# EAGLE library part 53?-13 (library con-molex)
CONNECTOR wire to board 1.25 mm (.049 inch) pitch header

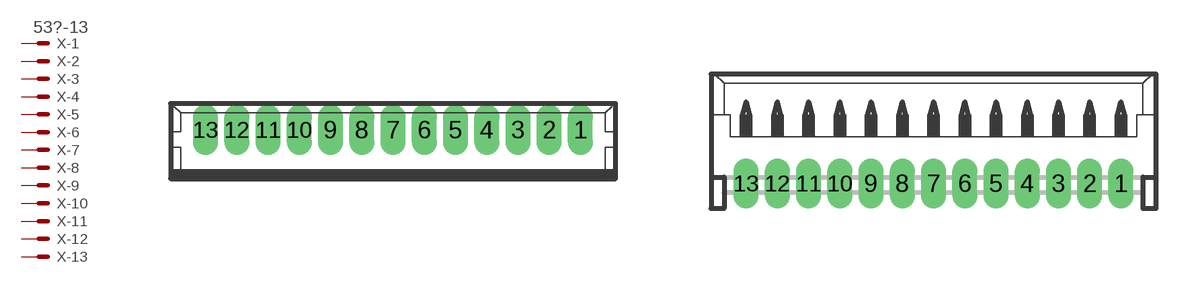
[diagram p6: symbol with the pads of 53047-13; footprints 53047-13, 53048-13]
Designator prefix X; gates -1=MV -2=M -3=M -4=M -5=M -6=M -7=M -8=M -9=M -10=M -11=M -12=M -13=M

## 53047-13 (MPN: 53047-1310-C; OC_FARNELL: 1012238; OC_NEWARK: 03N7646)  [53047-13]
1  -1:S  pas
2  -2:S  pas
3  -3:S  pas
4  -4:S  pas
5  -5:S  pas
6  -6:S  pas
7  -7:S  pas
8  -8:S  pas
9  -9:S  pas
10  -10:S  pas
11  -11:S  pas
12  -12:S  pas
13  -13:S  pas

## 53048-13 (MPN: 53048-1310-C; OC_FARNELL: unknown; OC_NEWARK: 03N7647)  [53048-13]
Pads as for 53047-13

## 53261-13 (MPN: 53261-1371; OC_FARNELL: 1756927; OC_NEWARK: 92M6827)  [53261-13]
Pads as for 53047-13

## 53398-13 (OC_FARNELL: unknown; OC_NEWARK: unknown)  [53398-13]
Pads as for 53047-13

## Footprint 53047-13 (pad centres in mm)
CONNECTOR wire to board 1.25 mm (.049 inch) pitch header straight Sourcxe: http://www.molex.com/pdm_docs/sd/530470210_sd.pdf
drill 0.5 pad 0.698 long: 1 7.5,0.45; 2 6.25,0.45; 3 5,0.45; 4 3.75,0.45; 5 2.5,0.45; 6 1.25,0.45; 7 0,0.45; 8 -1.25,0.45; 9 -2.5,0.45; 10 -3.75,0.45; 11 -5,0.45; 12 -6.25,0.45; 13 -7.5,0.45

## Footprint 53048-13 (pad centres in mm)
CONNECTOR wire to board 1.25 mm (.049 inch) pitch header right angle
drill 0.5 pad 0.698 long: 1 7.5,-1.25; 2 6.25,-1.25; 3 5,-1.25; 4 3.75,-1.25; 5 2.5,-1.25; 6 1.25,-1.25; 7 0,-1.25; 8 -1.25,-1.25; 9 -2.5,-1.25; 10 -3.75,-1.25; 11 -5,-1.25; 12 -6.25,-1.25; 13 -7.5,-1.25

## Footprint 53261-13 (pad centres in mm)
CONNECTOR wire to board 1.25 mm (.049 inch) pitch header SMT right angle
smd 0.8 x 2: 1 7.5,-2.5; 2 6.25,-2.5; 3 5,-2.5; 4 3.75,-2.5; 5 2.5,-2.5; 6 1.25,-2.5; 7 0,-2.5; 8 -1.25,-2.5; 9 -2.5,-2.5; 10 -3.75,-2.5; 11 -5,-2.5; 12 -6.25,-2.5; 13 -7.5,-2.5
smd 2.1 x 3: S1 10,0.625; S2 -10,0.625

## Footprint 53398-13 (pad centres in mm)
CONNECTOR wire to board 1.25 mm (.049 inch) pitch header SMT straight
smd 0.8 x 1.8: 1 7.5,-2.5; 2 6.25,-2.5; 3 5,-2.5; 4 3.75,-2.5; 5 2.5,-2.5; 6 1.25,-2.5; 7 0,-2.5; 8 -1.25,-2.5; 9 -2.5,-2.5; 10 -3.75,-2.5; 11 -5,-2.5; 12 -6.25,-2.5; 13 -7.5,-2.5
smd 2.1 x 3: S1 10,0.625; S2 -10,0.625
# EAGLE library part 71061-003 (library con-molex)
CONNECTOR 68-pin 1.27mm (.050 inch) pitch SCSI+ unshielded receptacle right angle all plastic

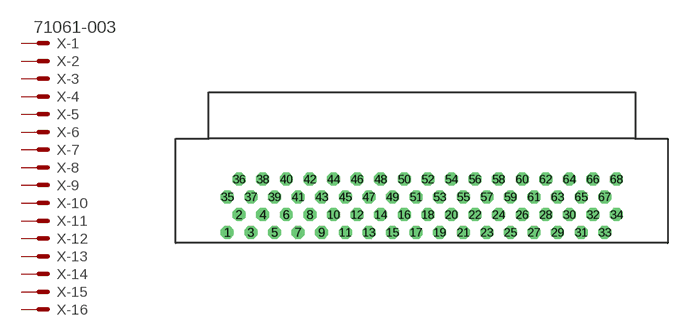
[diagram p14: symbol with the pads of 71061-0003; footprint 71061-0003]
Designator prefix X; gates -1=MV -2=M -3=M -4=M -5=M -6=M -7=M -8=M -9=M -10=M -11=M -12=M -13=M -14=M -15=M -16=M -17=M -18=M -19=M -20=M -21=M -22=M -23=M -24=M -25=M -26=M -27=M -28=M -29=M -30=M -31=M -32=M -33=M -34=M -35=M -36=M -37=M -38=M -39=M -40=M -41=M -42=M -43=M -44=M -45=M -46=M -47=M -48=M -49=M -50=M -51=M -52=M -53=M -54=M -55=M -56=M -57=M -58=M -59=M -60=M -61=M -62=M -63=M -64=M -65=M -66=M -67=M -68=M

## 71061-003 (OC_FARNELL: unknown; OC_NEWARK: unknown)  [71061-0003]
1  -1:S  pas
2  -2:S  pas
3  -3:S  pas
4  -4:S  pas
5  -5:S  pas
6  -6:S  pas
7  -7:S  pas
8  -8:S  pas
9  -9:S  pas
10  -10:S  pas
11  -11:S  pas
12  -12:S  pas
13  -13:S  pas
14  -14:S  pas
15  -15:S  pas
16  -16:S  pas
17  -17:S  pas
18  -18:S  pas
19  -19:S  pas
20  -20:S  pas
21  -21:S  pas
22  -22:S  pas
23  -23:S  pas
24  -24:S  pas
25  -25:S  pas
26  -26:S  pas
27  -27:S  pas
28  -28:S  pas
29  -29:S  pas
30  -30:S  pas
31  -31:S  pas
32  -32:S  pas
33  -33:S  pas
34  -34:S  pas
35  -35:S  pas
36  -36:S  pas
37  -37:S  pas
38  -38:S  pas
39  -39:S  pas
40  -40:S  pas
41  -41:S  pas
42  -42:S  pas
43  -43:S  pas
44  -44:S  pas
45  -45:S  pas
46  -46:S  pas
47  -47:S  pas
48  -48:S  pas
49  -49:S  pas
50  -50:S  pas
51  -51:S  pas
52  -52:S  pas
53  -53:S  pas
54  -54:S  pas
55  -55:S  pas
56  -56:S  pas
57  -57:S  pas
58  -58:S  pas
59  -59:S  pas
60  -60:S  pas
61  -61:S  pas
62  -62:S  pas
63  -63:S  pas
64  -64:S  pas
65  -65:S  pas
66  -66:S  pas
67  -67:S  pas
68  -68:S  pas

## Footprint 71061-0003 (pad centres in mm)
CONNECTOR 68-pin 1.27mm (.050 inch) pitch SCSI+ unshielded receptacle, right angle, all plastic Source: http://www.molex.com/product/io/71061.html http://www.molex.com .. 710610003_sd.pdf
drill 0.813 pad 1.397 octagon: 1 -20.955,-5.73; 2 -19.685,-3.82; 3 -18.415,-5.73; 4 -17.145,-3.82; 5 -15.875,-5.73; 6 -14.605,-3.82; 7 -13.335,-5.73; 8 -12.065,-3.82; 9 -10.795,-5.73; 10 -9.525,-3.82; 11 -8.255,-5.73; 12 -6.985,-3.82; 13 -5.715,-5.73; 14 -4.445,-3.82; 15 -3.175,-5.73; 16 -1.905,-3.82; 17 -0.635,-5.73; 18 0.635,-3.82; 19 1.905,-5.73; 20 3.175,-3.82; 21 4.445,-5.73; 22 5.715,-3.82; 23 6.985,-5.73; 24 8.255,-3.82; 25 9.525,-5.73; 26 10.795,-3.82; 27 12.065,-5.73; 28 13.335,-3.82; 29 14.605,-5.73; 30 15.875,-3.82; 31 17.145,-5.73; 32 18.415,-3.82; 33 19.685,-5.73; 34 20.955,-3.82; 35 -20.955,-1.91; 36 -19.685,0; 37 -18.415,-1.91; 38 -17.145,0; 39 -15.875,-1.91; 40 -14.605,0; 41 -13.335,-1.91; 42 -12.065,0; 43 -10.795,-1.91; 44 -9.525,0; 45 -8.255,-1.91; 46 -6.985,0; 47 -5.715,-1.91; 48 -4.445,0; 49 -3.175,-1.91; 50 -1.905,0; 51 -0.635,-1.91; 52 0.635,0; 53 1.905,-1.91; 54 3.175,0; 55 4.445,-1.91; 56 5.715,0; 57 6.985,-1.91; 58 8.255,0; 59 9.525,-1.91; 60 10.795,0; 61 12.065,-1.91; 62 13.335,0; 63 14.605,-1.91; 64 15.875,0; 65 17.145,-1.91; 66 18.415,0; 67 19.685,-1.91; 68 20.955,0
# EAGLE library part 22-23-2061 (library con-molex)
.100" (2.54mm) Center Header - 6 Pin

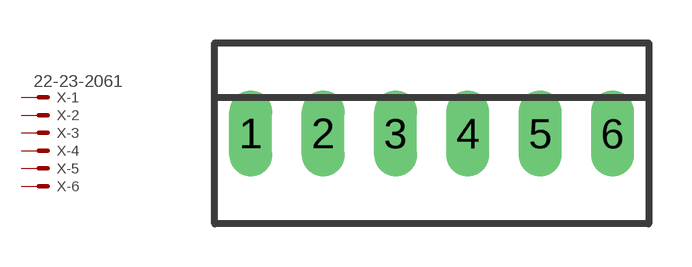
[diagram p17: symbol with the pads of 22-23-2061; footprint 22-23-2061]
Designator prefix X; gates -1=MV -2=M -3=M -4=M -5=M -6=M

## 22-23-2061 (MF: MOLEX; MPN: 22-23-2061; OC_FARNELL: 1462922; OC_NEWARK: 27C1933)  [22-23-2061]
1  -1:S  pas
2  -2:S  pas
3  -3:S  pas
4  -4:S  pas
5  -5:S  pas
6  -6:S  pas

## Footprint 22-23-2061 (pad centres in mm)
.100" (2.54mm) Center Header - 6 Pin
drill 1 long: 1 -6.35,0; 2 -3.81,0; 3 -1.27,0; 4 1.27,0; 5 3.81,0; 6 6.35,0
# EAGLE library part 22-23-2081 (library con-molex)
.100" (2.54mm) Center Header - 8 Pin

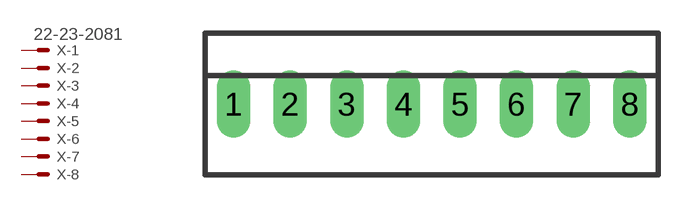
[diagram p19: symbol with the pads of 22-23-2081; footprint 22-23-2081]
Designator prefix X; gates -1=MV -2=M -3=M -4=M -5=M -6=M -7=M -8=M

## 22-23-2081 (MF: MOLEX; MPN: 22-23-2081; OC_FARNELL: 1756826; OC_NEWARK: 01C7592)  [22-23-2081]
1  -1:S  pas
2  -2:S  pas
3  -3:S  pas
4  -4:S  pas
5  -5:S  pas
6  -6:S  pas
7  -7:S  pas
8  -8:S  pas

## Footprint 22-23-2081 (pad centres in mm)
.100" (2.54mm) Center Header - 8 Pin
drill 1 long: 1 -8.89,0; 2 -6.35,0; 3 -3.81,0; 4 -1.27,0; 5 1.27,0; 6 3.81,0; 7 6.35,0; 8 8.89,0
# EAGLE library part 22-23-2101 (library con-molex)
.100" (2.54mm) Center Header - 10 Pin

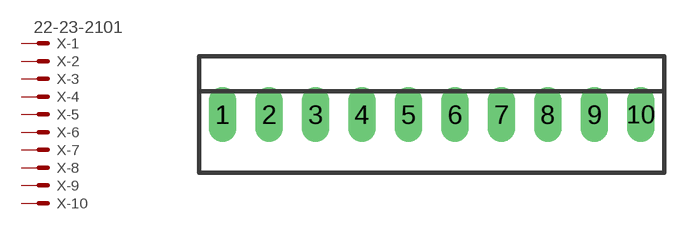
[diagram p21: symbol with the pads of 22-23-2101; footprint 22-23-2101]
Designator prefix X; gates -1=MV -2=M -3=M -4=M -5=M -6=M -7=M -8=M -9=M -10=M

## 22-23-2101 (MF: MOLEX; MPN: 22-23-2101; OC_FARNELL: 1756828; OC_NEWARK: 94C0765)  [22-23-2101]
1  -1:S  pas
2  -2:S  pas
3  -3:S  pas
4  -4:S  pas
5  -5:S  pas
6  -6:S  pas
7  -7:S  pas
8  -8:S  pas
9  -9:S  pas
10  -10:S  pas

## Footprint 22-23-2101 (pad centres in mm)
.100" (2.54mm) Center Header - 10 Pin
drill 1 long: 1 -11.43,0; 2 -8.89,0; 3 -6.35,0; 4 -3.81,0; 5 -1.27,0; 6 1.27,0; 7 3.81,0; 8 6.35,0; 9 8.89,0; 10 11.43,0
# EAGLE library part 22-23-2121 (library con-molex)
.100" (2.54mm) Center Header - 12 Pin

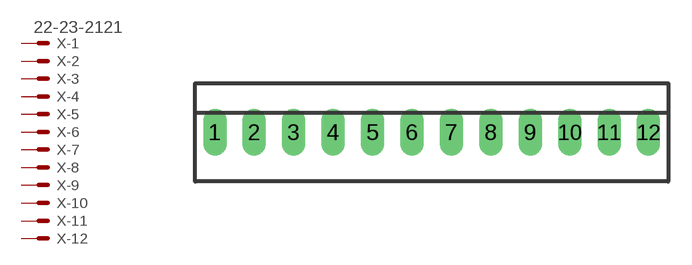
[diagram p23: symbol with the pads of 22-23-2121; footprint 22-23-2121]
Designator prefix X; gates -1=MV -2=M -3=M -4=M -5=M -6=M -7=M -8=M -9=M -10=M -11=M -12=M

## 22-23-2121 (MF: MOLEX; MPN: 22-23-2121; OC_FARNELL: 1462935; OC_NEWARK: 56H0456)  [22-23-2121]
1  -1:S  pas
2  -2:S  pas
3  -3:S  pas
4  -4:S  pas
5  -5:S  pas
6  -6:S  pas
7  -7:S  pas
8  -8:S  pas
9  -9:S  pas
10  -10:S  pas
11  -11:S  pas
12  -12:S  pas

## Footprint 22-23-2121 (pad centres in mm)
.100" (2.54mm) Center Header - 12 Pin
drill 1 long: 1 -13.97,0; 2 -11.43,0; 3 -8.89,0; 4 -6.35,0; 5 -3.81,0; 6 -1.27,0; 7 1.27,0; 8 3.81,0; 9 6.35,0; 10 8.89,0; 11 11.43,0; 12 13.97,0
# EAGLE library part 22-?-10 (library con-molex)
CONNECTOR wire to board 2.54 mm (.1 inch) pitch header

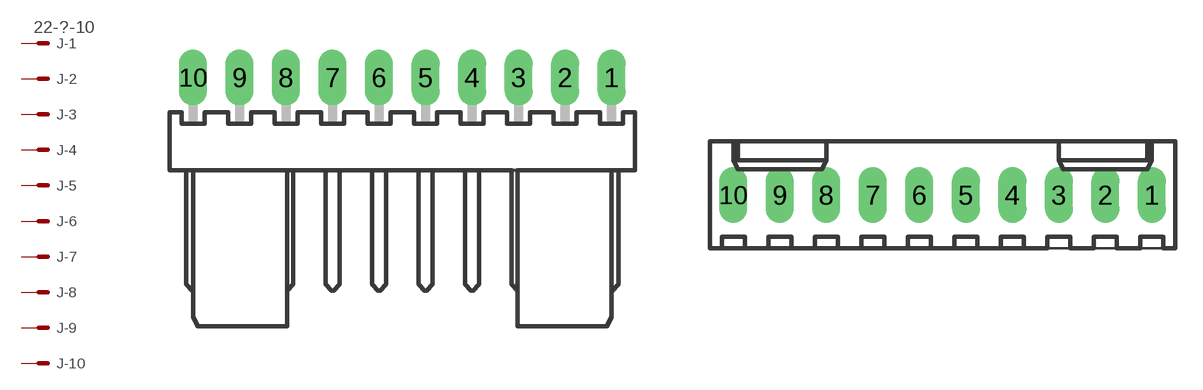
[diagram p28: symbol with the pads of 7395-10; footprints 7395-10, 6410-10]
Designator prefix J; gates -1=MV -2=M -3=M -4=M -5=M -6=M -7=M -8=M -9=M -10=M

## 22-05-7108-10 (OC_FARNELL: unknown; OC_NEWARK: unknown)  [7395-10]
1  -1:S  pas
2  -2:S  pas
3  -3:S  pas
4  -4:S  pas
5  -5:S  pas
6  -6:S  pas
7  -7:S  pas
8  -8:S  pas
9  -9:S  pas
10  -10:S  pas

## 22-27-2101-10 (OC_FARNELL: unknown; OC_NEWARK: unknown)  [6410-10]
Pads as for 7395-10

## Footprint 7395-10 (pad centres in mm)
MOLEX 2.54mm KK RA CONNECTOR Fixed Orientation
drill 1.016 long: 1 11.43,0; 2 8.89,0; 3 6.35,0; 4 3.81,0; 5 1.27,0; 6 -1.27,0; 7 -3.81,0; 8 -6.35,0; 9 -8.89,0; 10 -11.43,0

## Footprint 6410-10 (pad centres in mm)
MOLEX 2.54mm KK CONNECTOR
drill 1.016 long: 1 11.43,0; 2 8.89,0; 3 6.35,0; 4 3.81,0; 5 1.27,0; 6 -1.27,0; 7 -3.81,0; 8 -6.35,0; 9 -8.89,0; 10 -11.43,0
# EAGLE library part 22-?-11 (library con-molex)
CONNECTOR wire to board 2.54 mm (.1 inch) pitch header

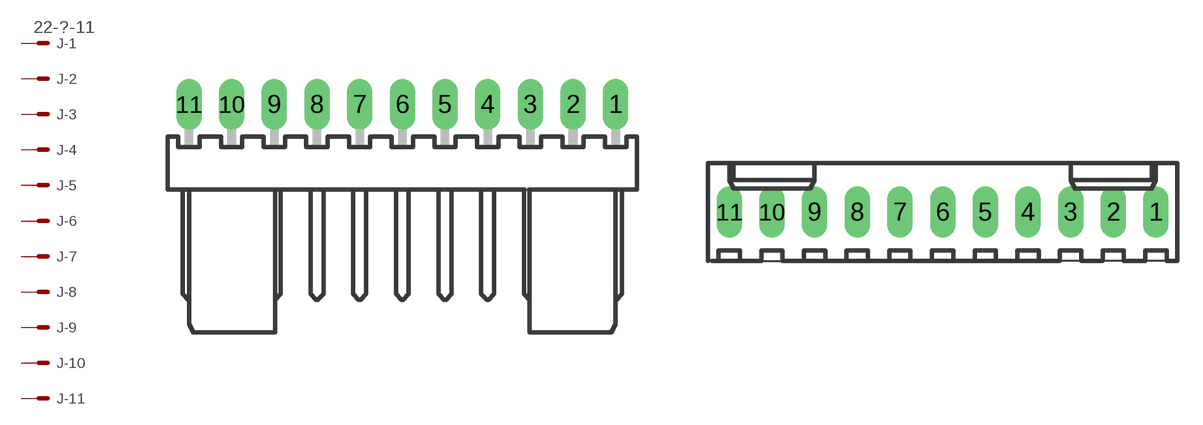
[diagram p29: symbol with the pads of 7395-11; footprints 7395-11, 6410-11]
Designator prefix J; gates -1=MV -2=M -3=M -4=M -5=M -6=M -7=M -8=M -9=M -10=M -11=M

## 22-05-7118-11 (OC_FARNELL: unknown; OC_NEWARK: unknown)  [7395-11]
1  -1:S  pas
2  -2:S  pas
3  -3:S  pas
4  -4:S  pas
5  -5:S  pas
6  -6:S  pas
7  -7:S  pas
8  -8:S  pas
9  -9:S  pas
10  -10:S  pas
11  -11:S  pas

## 22-27-2111-11 (OC_FARNELL: unknown; OC_NEWARK: unknown)  [6410-11]
Pads as for 7395-11

## Footprint 7395-11 (pad centres in mm)
MOLEX 2.54mm KK RA CONNECTOR Fixed Orientation
drill 1.016 long: 1 12.7,0; 2 10.16,0; 3 7.62,0; 4 5.08,0; 5 2.54,0; 6 0,0; 7 -2.54,0; 8 -5.08,0; 9 -7.62,0; 10 -10.16,0; 11 -12.7,0

## Footprint 6410-11 (pad centres in mm)
MOLEX 2.54mm KK CONNECTOR
drill 1.016 long: 1 12.7,0; 2 10.16,0; 3 7.62,0; 4 5.08,0; 5 2.54,0; 6 0,0; 7 -2.54,0; 8 -5.08,0; 9 -7.62,0; 10 -10.16,0; 11 -12.7,0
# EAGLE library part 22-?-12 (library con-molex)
CONNECTOR wire to board 2.54 mm (.1 inch) pitch header

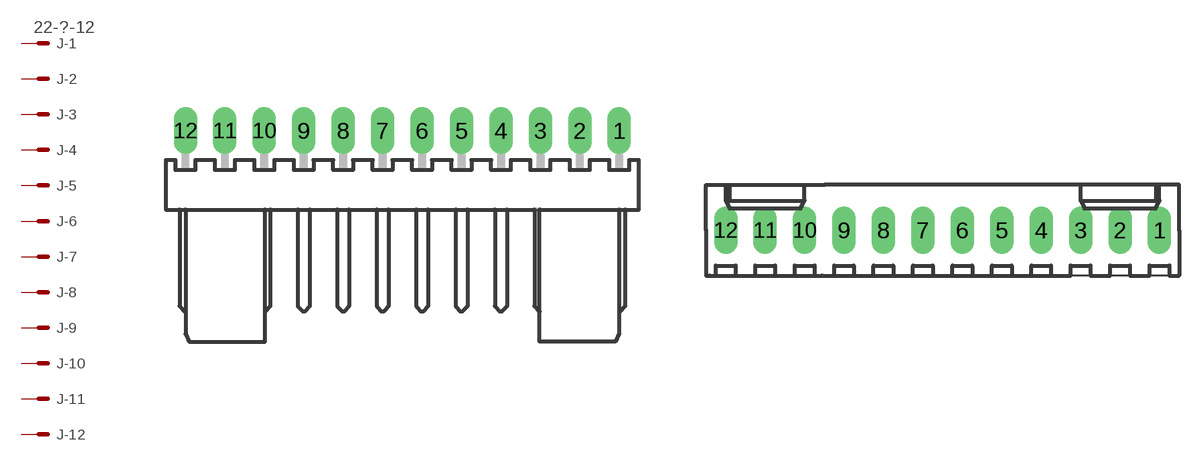
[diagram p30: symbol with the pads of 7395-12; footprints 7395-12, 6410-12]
Designator prefix J; gates -1=MV -2=M -3=M -4=M -5=M -6=M -7=M -8=M -9=M -10=M -11=M -12=M

## 22-05-7128-12 (OC_FARNELL: unknown; OC_NEWARK: unknown)  [7395-12]
1  -1:S  pas
2  -2:S  pas
3  -3:S  pas
4  -4:S  pas
5  -5:S  pas
6  -6:S  pas
7  -7:S  pas
8  -8:S  pas
9  -9:S  pas
10  -10:S  pas
11  -11:S  pas
12  -12:S  pas

## 22-27-2121-12 (OC_FARNELL: unknown; OC_NEWARK: unknown)  [6410-12]
Pads as for 7395-12

## Footprint 7395-12 (pad centres in mm)
MOLEX 2.54mm KK RA CONNECTOR Fixed Orientation
drill 1.016 long: 1 13.97,0; 2 11.43,0; 3 8.89,0; 4 6.35,0; 5 3.81,0; 6 1.27,0; 7 -1.27,0; 8 -3.81,0; 9 -6.35,0; 10 -8.89,0; 11 -11.43,0; 12 -13.97,0

## Footprint 6410-12 (pad centres in mm)
MOLEX 2.54mm KK CONNECTOR
drill 1.016 long: 1 13.97,0; 2 11.43,0; 3 8.89,0; 4 6.35,0; 5 3.81,0; 6 1.27,0; 7 -1.27,0; 8 -3.81,0; 9 -6.35,0; 10 -8.89,0; 11 -11.43,0; 12 -13.97,0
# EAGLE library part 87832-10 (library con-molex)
Milli-Grid Header 2.00mm (.079") Pitch

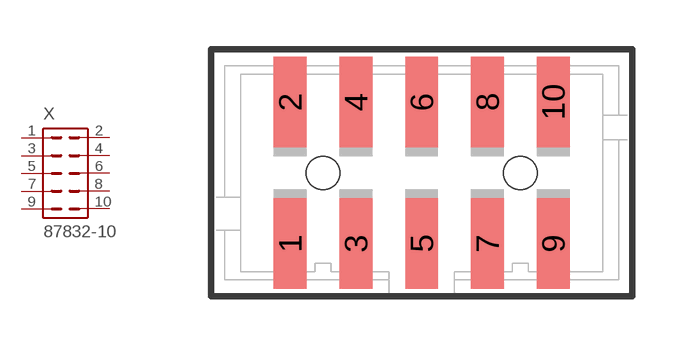
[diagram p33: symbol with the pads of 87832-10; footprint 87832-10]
Designator prefix X

## 87832-10 (OC_FARNELL: unknown; OC_NEWARK: unknown)  [87832-10]
1  1  pas
2  2  pas
3  3  pas
4  4  pas
5  5  pas
6  6  pas
7  7  pas
8  8  pas
9  9  pas
10  10  pas

## Footprint 87832-10 (pad centres in mm)
PCB Headers 2.00mm (.079") Pitch Milli-Grid Header, Vertical, Shrouded
smd 1 x 2.75: 1 -4,-2.15; 2 -4,2.15; 3 -2,-2.15; 4 -2,2.15; 5 0,-2.15; 6 0,2.15; 7 2,-2.15; 8 2,2.15; 9 4,-2.15; 10 4,2.15
hole 1 at -3,0
hole 1 at 3,0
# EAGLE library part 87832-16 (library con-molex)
Milli-Grid Header 2.00mm (.079") Pitch

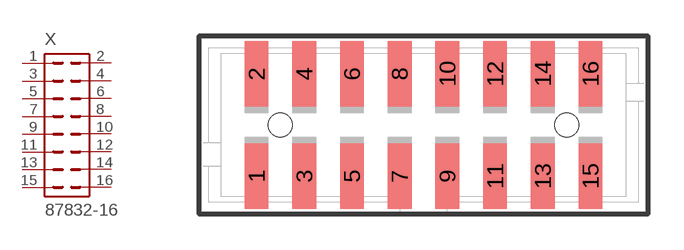
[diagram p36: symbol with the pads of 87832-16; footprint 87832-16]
Designator prefix X

## 87832-16 (OC_FARNELL: 1756949; OC_NEWARK: unknown)  [87832-16]
1  1  pas
2  2  pas
3  3  pas
4  4  pas
5  5  pas
6  6  pas
7  7  pas
8  8  pas
9  9  pas
10  10  pas
11  11  pas
12  12  pas
13  13  pas
14  14  pas
15  15  pas
16  16  pas

## Footprint 87832-16 (pad centres in mm)
PCB Headers 2.00mm (.079") Pitch Milli-Grid Header, Vertical, Shrouded
smd 1 x 2.75: 1 -7,-2.15; 2 -7,2.15; 3 -5,-2.15; 4 -5,2.15; 5 -3,-2.15; 6 -3,2.15; 7 -1,-2.15; 8 -1,2.15; 9 1,-2.15; 10 1,2.15; 11 3,-2.15; 12 3,2.15; 13 5,-2.15; 14 5,2.15; 15 7,-2.15; 16 7,2.15
hole 1 at -6,0
hole 1 at 6,0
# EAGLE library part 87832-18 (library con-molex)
Milli-Grid Header 2.00mm (.079") Pitch

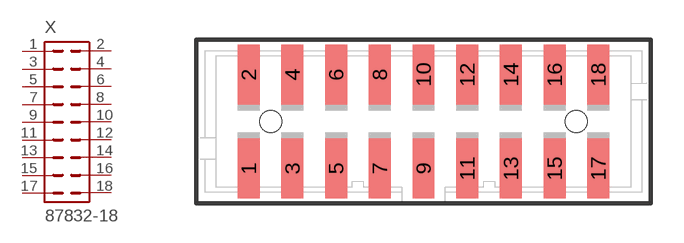
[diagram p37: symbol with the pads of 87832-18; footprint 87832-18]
Designator prefix X

## 87832-18 (OC_FARNELL: unknown; OC_NEWARK: unknown)  [87832-18]
1  1  pas
2  2  pas
3  3  pas
4  4  pas
5  5  pas
6  6  pas
7  7  pas
8  8  pas
9  9  pas
10  10  pas
11  11  pas
12  12  pas
13  13  pas
14  14  pas
15  15  pas
16  16  pas
17  17  pas
18  18  pas

## Footprint 87832-18 (pad centres in mm)
PCB Headers 2.00mm (.079") Pitch Milli-Grid Header, Vertical, Shrouded
smd 1 x 2.75: 1 -8,-2.15; 2 -8,2.15; 3 -6,-2.15; 4 -6,2.15; 5 -4,-2.15; 6 -4,2.15; 7 -2,-2.15; 8 -2,2.15; 9 0,-2.15; 10 0,2.15; 11 2,-2.15; 12 2,2.15; 13 4,-2.15; 14 4,2.15; 15 6,-2.15; 16 6,2.15; 17 8,-2.15; 18 8,2.15
hole 1 at -7,0
hole 1 at 7,0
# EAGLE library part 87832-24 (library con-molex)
Milli-Grid Header 2.00mm (.079") Pitch

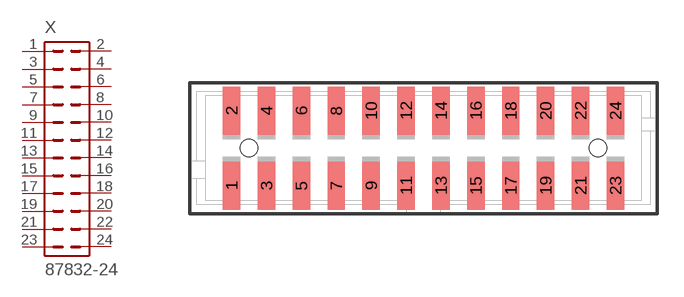
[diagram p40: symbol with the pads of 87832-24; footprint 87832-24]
Designator prefix X

## 87832-24 (OC_FARNELL: unknown; OC_NEWARK: unknown)  [87832-24]
1  1  pas
2  2  pas
3  3  pas
4  4  pas
5  5  pas
6  6  pas
7  7  pas
8  8  pas
9  9  pas
10  10  pas
11  11  pas
12  12  pas
13  13  pas
14  14  pas
15  15  pas
16  16  pas
17  17  pas
18  18  pas
19  19  pas
20  20  pas
21  21  pas
22  22  pas
23  23  pas
24  24  pas

## Footprint 87832-24 (pad centres in mm)
PCB Headers 2.00mm (.079") Pitch Milli-Grid Header, Vertical, Shrouded
smd 1 x 2.75: 1 -11,-2.15; 2 -11,2.15; 3 -9,-2.15; 4 -9,2.15; 5 -7,-2.15; 6 -7,2.15; 7 -5,-2.15; 8 -5,2.15; 9 -3,-2.15; 10 -3,2.15; 11 -1,-2.15; 12 -1,2.15; 13 1,-2.15; 14 1,2.15; 15 3,-2.15; 16 3,2.15; 17 5,-2.15; 18 5,2.15; 19 7,-2.15; 20 7,2.15; 21 9,-2.15; 22 9,2.15; 23 11,-2.15; 24 11,2.15
hole 1 at -10,0
hole 1 at 10,0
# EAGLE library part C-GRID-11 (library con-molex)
CONNECTOR wire to board 2.54 mm (0.100") pitch header

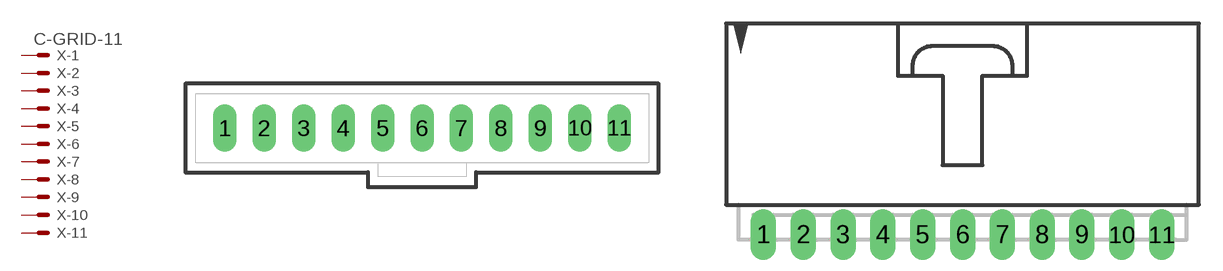
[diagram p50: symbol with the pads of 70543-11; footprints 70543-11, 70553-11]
Designator prefix X; gates -1=MV -2=M -3=M -4=M -5=M -6=M -7=M -8=M -9=M -10=M -11=M

## C-GRID-11-70543 (OC_FARNELL: unknown; OC_NEWARK: unknown)  [70543-11]
1  -1:S  pas
2  -2:S  pas
3  -3:S  pas
4  -4:S  pas
5  -5:S  pas
6  -6:S  pas
7  -7:S  pas
8  -8:S  pas
9  -9:S  pas
10  -10:S  pas
11  -11:S  pas

## C-GRID-11-70553 (OC_FARNELL: unknown; OC_NEWARK: unknown)  [70553-11]
Pads as for 70543-11

## C-GRID-11-74099 (OC_FARNELL: unknown; OC_NEWARK: unknown)  [74099-11]
Pads as for 70543-11

## C-GRID-11-15-91 (OC_FARNELL: unknown; OC_NEWARK: unknown)  [15-91-11]
Pads as for 70543-11

## Footprint 70543-11 (pad centres in mm)
C-Grid SL Connector vertical, 11 pin
drill 1.016 long: 1 -12.7,0; 2 -10.16,0; 3 -7.62,0; 4 -5.08,0; 5 -2.54,0; 6 0,0; 7 2.54,0; 8 5.08,0; 9 7.62,0; 10 10.16,0; 11 12.7,0

## Footprint 70553-11 (pad centres in mm)
C-Grid SL Connector right angle, 11 pin
drill 1.092 long: 1 -12.7,-7.62; 2 -10.16,-7.62; 3 -7.62,-7.62; 4 -5.08,-7.62; 5 -2.54,-7.62; 6 0,-7.62; 7 2.54,-7.62; 8 5.08,-7.62; 9 7.62,-7.62; 10 10.16,-7.62; 11 12.7,-7.62

## Footprint 74099-11 (pad centres in mm)
C-Grid SL Connector vertical SMD, 11 pin
smd 1.27 x 3.175: 1 -12.7,-2.223; 2 -10.16,2.223; 3 -7.62,-2.223; 4 -5.08,2.223; 5 -2.54,-2.223; 6 0,2.223; 7 2.54,-2.223; 8 5.08,2.223; 9 7.62,-2.223; 10 10.16,2.223; 11 12.7,-2.223

## Footprint 15-91-11 (pad centres in mm)
C-Grid SL Connector right angle SMD, 11 pin
smd 1.651 x 5.334: 1 -12.7,-10.795; 2 -10.16,-10.795; 3 -7.62,-10.795; 4 -5.08,-10.795; 5 -2.54,-10.795; 6 0,-10.795; 7 2.54,-10.795; 8 5.08,-10.795; 9 7.62,-10.795; 10 10.16,-10.795; 11 12.7,-10.795
hole 3.404 at -14.097,0.838
hole 3.404 at 14.097,0.838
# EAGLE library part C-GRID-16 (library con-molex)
CONNECTOR wire to board 2.54 mm (0.100") pitch header

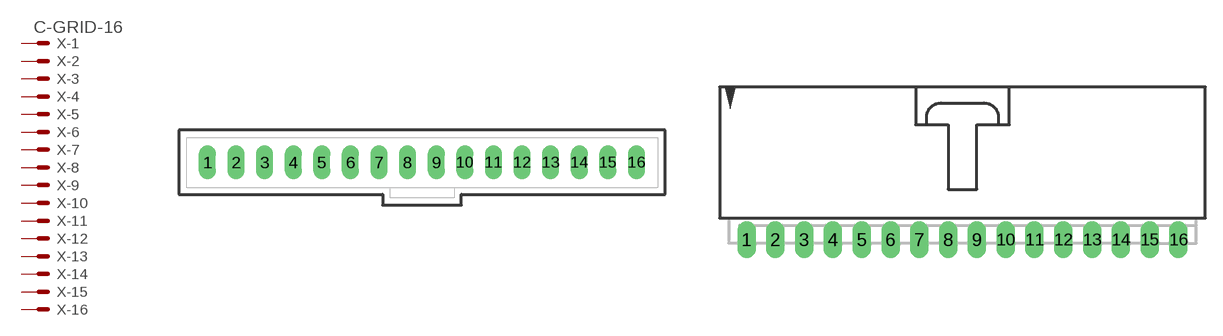
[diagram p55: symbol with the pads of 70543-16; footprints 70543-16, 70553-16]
Designator prefix X; gates -1=MV -2=M -3=M -4=M -5=M -6=M -7=M -8=M -9=M -10=M -11=M -12=M -13=M -14=M -15=M -16=M

## C-GRID-16-70543 (OC_FARNELL: unknown; OC_NEWARK: unknown)  [70543-16]
1  -1:S  pas
2  -2:S  pas
3  -3:S  pas
4  -4:S  pas
5  -5:S  pas
6  -6:S  pas
7  -7:S  pas
8  -8:S  pas
9  -9:S  pas
10  -10:S  pas
11  -11:S  pas
12  -12:S  pas
13  -13:S  pas
14  -14:S  pas
15  -15:S  pas
16  -16:S  pas

## C-GRID-16-70553 (OC_FARNELL: unknown; OC_NEWARK: unknown)  [70553-16]
Pads as for 70543-16

## C-GRID-16-74099 (OC_FARNELL: unknown; OC_NEWARK: unknown)  [74099-16]
Pads as for 70543-16

## C-GRID-16-15-91 (OC_FARNELL: unknown; OC_NEWARK: unknown)  [15-91-16]
Pads as for 70543-16

## Footprint 70543-16 (pad centres in mm)
C-Grid SL Connector vertical, 16 pin
drill 1.016 long: 1 -19.05,0; 2 -16.51,0; 3 -13.97,0; 4 -11.43,0; 5 -8.89,0; 6 -6.35,0; 7 -3.81,0; 8 -1.27,0; 9 1.27,0; 10 3.81,0; 11 6.35,0; 12 8.89,0; 13 11.43,0; 14 13.97,0; 15 16.51,0; 16 19.05,0

## Footprint 70553-16 (pad centres in mm)
C-Grid SL Connector right angle, 16 pin
drill 1.092 long: 1 -19.05,-7.62; 2 -16.51,-7.62; 3 -13.97,-7.62; 4 -11.43,-7.62; 5 -8.89,-7.62; 6 -6.35,-7.62; 7 -3.81,-7.62; 8 -1.27,-7.62; 9 1.27,-7.62; 10 3.81,-7.62; 11 6.35,-7.62; 12 8.89,-7.62; 13 11.43,-7.62; 14 13.97,-7.62; 15 16.51,-7.62; 16 19.05,-7.62

## Footprint 74099-16 (pad centres in mm)
C-Grid SL Connector vertical SMD, 16 pin
smd 1.27 x 3.175: 1 -19.05,-2.223; 2 -16.51,2.223; 3 -13.97,-2.223; 4 -11.43,2.223; 5 -8.89,-2.223; 6 -6.35,2.223; 7 -3.81,-2.223; 8 -1.27,2.223; 9 1.27,-2.223; 10 3.81,2.223; 11 6.35,-2.223; 12 8.89,2.223; 13 11.43,-2.223; 14 13.97,2.223; 15 16.51,-2.223; 16 19.05,2.223

## Footprint 15-91-16 (pad centres in mm)
C-Grid SL Connector right angle SMD, 16 pin
smd 1.651 x 5.334: 1 -19.05,-10.795; 2 -16.51,-10.795; 3 -13.97,-10.795; 4 -11.43,-10.795; 5 -8.89,-10.795; 6 -6.35,-10.795; 7 -3.81,-10.795; 8 -1.27,-10.795; 9 1.27,-10.795; 10 3.81,-10.795; 11 6.35,-10.795; 12 8.89,-10.795; 13 11.43,-10.795; 14 13.97,-10.795; 15 16.51,-10.795; 16 19.05,-10.795
hole 3.404 at -20.447,0.838
hole 3.404 at 20.447,0.838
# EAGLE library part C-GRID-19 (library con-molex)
CONNECTOR wire to board 2.54 mm (0.100") pitch header

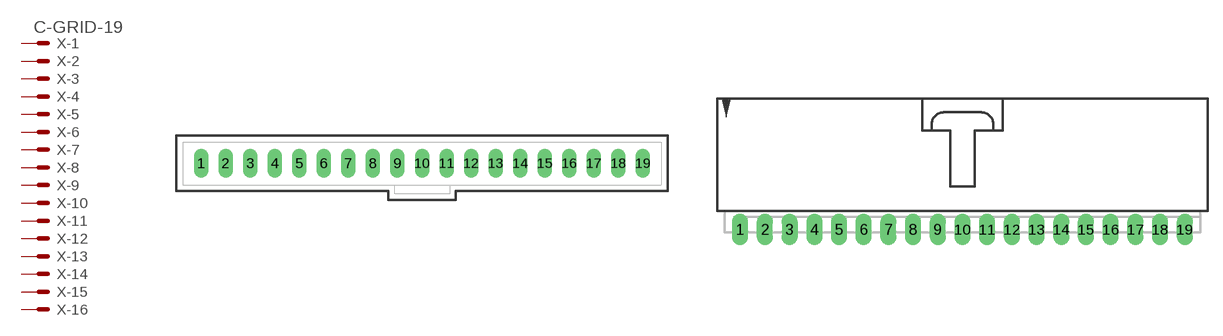
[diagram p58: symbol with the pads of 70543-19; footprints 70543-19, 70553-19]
Designator prefix X; gates -1=MV -2=M -3=M -4=M -5=M -6=M -7=M -8=M -9=M -10=M -11=M -12=M -13=M -14=M -15=M -16=M -17=M -18=M -19=M

## C-GRID-19-70543 (OC_FARNELL: unknown; OC_NEWARK: unknown)  [70543-19]
1  -1:S  pas
2  -2:S  pas
3  -3:S  pas
4  -4:S  pas
5  -5:S  pas
6  -6:S  pas
7  -7:S  pas
8  -8:S  pas
9  -9:S  pas
10  -10:S  pas
11  -11:S  pas
12  -12:S  pas
13  -13:S  pas
14  -14:S  pas
15  -15:S  pas
16  -16:S  pas
17  -17:S  pas
18  -18:S  pas
19  -19:S  pas

## C-GRID-19-70553 (OC_FARNELL: unknown; OC_NEWARK: unknown)  [70553-19]
Pads as for 70543-19

## Footprint 70543-19 (pad centres in mm)
C-Grid SL Connector vertical, 19 pin
drill 1.016 long: 1 -22.86,0; 2 -20.32,0; 3 -17.78,0; 4 -15.24,0; 5 -12.7,0; 6 -10.16,0; 7 -7.62,0; 8 -5.08,0; 9 -2.54,0; 10 0,0; 11 2.54,0; 12 5.08,0; 13 7.62,0; 14 10.16,0; 15 12.7,0; 16 15.24,0; 17 17.78,0; 18 20.32,0; 19 22.86,0

## Footprint 70553-19 (pad centres in mm)
C-Grid SL Connector right angle, 19 pin
drill 1.092 long: 1 -22.86,-7.62; 2 -20.32,-7.62; 3 -17.78,-7.62; 4 -15.24,-7.62; 5 -12.7,-7.62; 6 -10.16,-7.62; 7 -7.62,-7.62; 8 -5.08,-7.62; 9 -2.54,-7.62; 10 0,-7.62; 11 2.54,-7.62; 12 5.08,-7.62; 13 7.62,-7.62; 14 10.16,-7.62; 15 12.7,-7.62; 16 15.24,-7.62; 17 17.78,-7.62; 18 20.32,-7.62; 19 22.86,-7.62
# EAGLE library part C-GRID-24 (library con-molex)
CONNECTOR wire to board 2.54 mm (0.100") pitch header

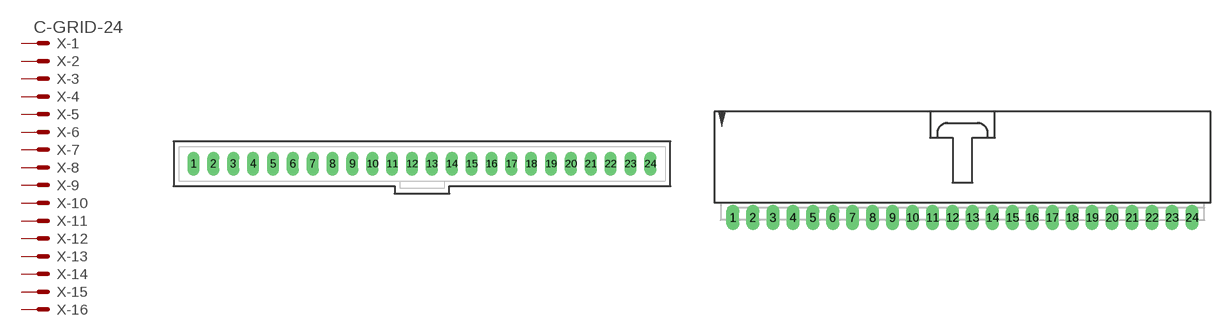
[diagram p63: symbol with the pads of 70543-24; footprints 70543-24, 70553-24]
Designator prefix X; gates -1=MV -2=M -3=M -4=M -5=M -6=M -7=M -8=M -9=M -10=M -11=M -12=M -13=M -14=M -15=M -16=M -17=M -18=M -19=M -20=M -21=M -22=M -23=M -24=M

## C-GRID-24-70543 (OC_FARNELL: unknown; OC_NEWARK: unknown)  [70543-24]
1  -1:S  pas
2  -2:S  pas
3  -3:S  pas
4  -4:S  pas
5  -5:S  pas
6  -6:S  pas
7  -7:S  pas
8  -8:S  pas
9  -9:S  pas
10  -10:S  pas
11  -11:S  pas
12  -12:S  pas
13  -13:S  pas
14  -14:S  pas
15  -15:S  pas
16  -16:S  pas
17  -17:S  pas
18  -18:S  pas
19  -19:S  pas
20  -20:S  pas
21  -21:S  pas
22  -22:S  pas
23  -23:S  pas
24  -24:S  pas

## C-GRID-24-70553 (OC_FARNELL: unknown; OC_NEWARK: unknown)  [70553-24]
Pads as for 70543-24

## Footprint 70543-24 (pad centres in mm)
C-Grid SL Connector vertical, 24 pin
drill 1.016 long: 1 -29.21,0; 2 -26.67,0; 3 -24.13,0; 4 -21.59,0; 5 -19.05,0; 6 -16.51,0; 7 -13.97,0; 8 -11.43,0; 9 -8.89,0; 10 -6.35,0; 11 -3.81,0; 12 -1.27,0; 13 1.27,0; 14 3.81,0; 15 6.35,0; 16 8.89,0; 17 11.43,0; 18 13.97,0; 19 16.51,0; 20 19.05,0; 21 21.59,0; 22 24.13,0; 23 26.67,0; 24 29.21,0

## Footprint 70553-24 (pad centres in mm)
C-Grid SL Connector right angle, 24 pin
drill 1.092 long: 1 -29.21,-7.62; 2 -26.67,-7.62; 3 -24.13,-7.62; 4 -21.59,-7.62; 5 -19.05,-7.62; 6 -16.51,-7.62; 7 -13.97,-7.62; 8 -11.43,-7.62; 9 -8.89,-7.62; 10 -6.35,-7.62; 11 -3.81,-7.62; 12 -1.27,-7.62; 13 1.27,-7.62; 14 3.81,-7.62; 15 6.35,-7.62; 16 8.89,-7.62; 17 11.43,-7.62; 18 13.97,-7.62; 19 16.51,-7.62; 20 19.05,-7.62; 21 21.59,-7.62; 22 24.13,-7.62; 23 26.67,-7.62; 24 29.21,-7.62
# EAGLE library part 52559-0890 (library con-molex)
FFC/FPC-to-Board 0.50mm (.020") SMT, Vertical, ZIF Receptacle Source: http://www.molex.com/product/ffc/52559.html

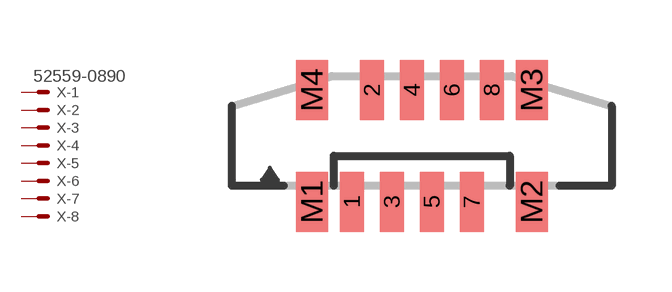
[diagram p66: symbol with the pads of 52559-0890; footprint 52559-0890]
Designator prefix X; gates -1=MV -2=M -3=M -4=M -5=M -6=M -7=M -8=M

## 52559-0890 (OC_FARNELL: unknown; OC_NEWARK: unknown)  [52559-0890]
1  -1:S  pas
2  -2:S  pas
3  -3:S  pas
4  -4:S  pas
5  -5:S  pas
6  -6:S  pas
7  -7:S  pas
8  -8:S  pas

## Footprint 52559-0890 (pad centres in mm)
FFC/FPC-to-Board 0.50mm (.020") SMT, Vertical, ZIF Receptacle Source: http://www.molex.com/product/ffc/52559.html
smd 0.6 x 1.5: 1 -1.75,-1.4; 2 -1.25,1.4; 3 -0.75,-1.4; 4 -0.25,1.4; 5 0.25,-1.4; 6 0.75,1.4; 7 1.25,-1.4; 8 1.75,1.4
smd 0.8 x 1.5: M1 -2.75,-1.4; M2 2.75,-1.4; M3 2.75,1.4; M4 -2.75,1.4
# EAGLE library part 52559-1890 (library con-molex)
FFC/FPC-to-Board 0.50mm (.020") SMT, Vertical, ZIF Receptacle Source: http://www.molex.com/product/ffc/52559.html

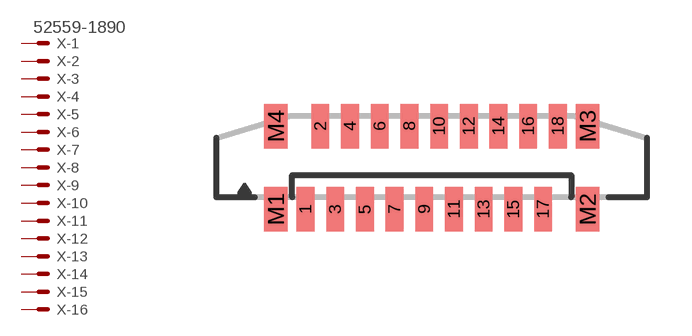
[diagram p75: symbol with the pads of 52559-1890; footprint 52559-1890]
Designator prefix X; gates -1=MV -2=M -3=M -4=M -5=M -6=M -7=M -8=M -9=M -10=M -11=M -12=M -13=M -14=M -15=M -16=M -17=M -18=M

## 52559-1890 (MPN: 52559-1890; OC_FARNELL: unknown; OC_NEWARK: 92M6187)  [52559-1890]
1  -1:S  pas
2  -2:S  pas
3  -3:S  pas
4  -4:S  pas
5  -5:S  pas
6  -6:S  pas
7  -7:S  pas
8  -8:S  pas
9  -9:S  pas
10  -10:S  pas
11  -11:S  pas
12  -12:S  pas
13  -13:S  pas
14  -14:S  pas
15  -15:S  pas
16  -16:S  pas
17  -17:S  pas
18  -18:S  pas

## Footprint 52559-1890 (pad centres in mm)
FFC/FPC-to-Board 0.50mm (.020") SMT, Vertical, ZIF Receptacle Source: http://www.molex.com/product/ffc/52559.html
smd 0.6 x 1.5: 1 -4.25,-1.4; 2 -3.75,1.4; 3 -3.25,-1.4; 4 -2.75,1.4; 5 -2.25,-1.4; 6 -1.75,1.4; 7 -1.25,-1.4; 8 -0.75,1.4; 9 -0.25,-1.4; 10 0.25,1.4; 11 0.75,-1.4; 12 1.25,1.4; 13 1.75,-1.4; 14 2.25,1.4; 15 2.75,-1.4; 16 3.25,1.4; 17 3.75,-1.4; 18 4.25,1.4
smd 0.8 x 1.5: M1 -5.25,-1.4; M2 5.25,-1.4; M3 5.25,1.4; M4 -5.25,1.4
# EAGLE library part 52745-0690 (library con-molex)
FFC/FPC-to-Board 0.50mm (.020") SMT Top Contact Right Angle, ZIF, Style Receptacle 52745 / 52435 Source: http://www.molex.com/product/ffc/52745.html

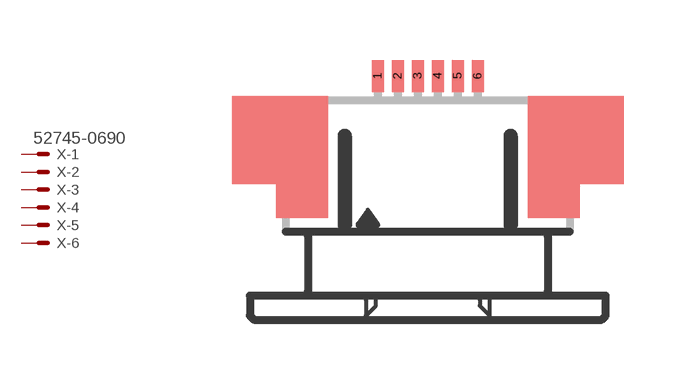
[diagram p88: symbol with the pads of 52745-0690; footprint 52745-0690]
Designator prefix X; gates -1=MV -2=M -3=M -4=M -5=M -6=M

## 52745-0690 (MPN: 52745-0690; OC_FARNELL: unknown; OC_NEWARK: 92M6374)  [52745-0690]
1  -1:S  pas
2  -2:S  pas
3  -3:S  pas
4  -4:S  pas
5  -5:S  pas
6  -6:S  pas

## Footprint 52745-0690 (pad centres in mm)
FFC/FPC-to-Board 0.50mm (.020") SMT Top Contact Right Angle, ZIF, Style Receptacle 52745 / 52435 Source: http://www.molex.com/product/ffc/52745.html
smd 0.3 x 0.8: 1 -1.25,2.5; 2 -0.75,2.5; 3 -0.25,2.5; 4 0.25,2.5; 5 0.75,2.5; 6 1.25,2.5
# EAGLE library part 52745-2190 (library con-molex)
FFC/FPC-to-Board 0.50mm (.020") SMT Top Contact Right Angle, ZIF, Style Receptacle 52745 / 52435 Source: http://www.molex.com/product/ffc/52745.html

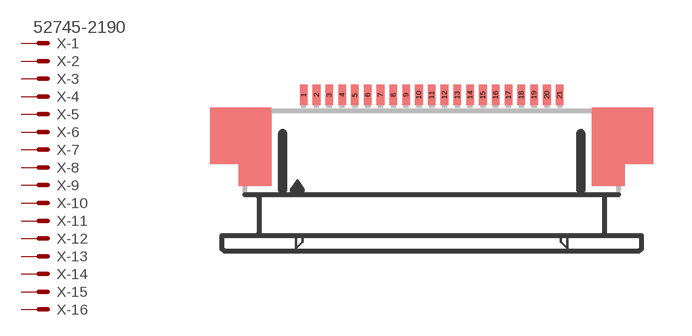
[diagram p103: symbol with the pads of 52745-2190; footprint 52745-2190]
Designator prefix X; gates -1=MV -2=M -3=M -4=M -5=M -6=M -7=M -8=M -9=M -10=M -11=M -12=M -13=M -14=M -15=M -16=M -17=M -18=M -19=M -20=M -21=M

## 52745-2190 (OC_FARNELL: unknown; OC_NEWARK: unknown)  [52745-2190]
1  -1:S  pas
2  -2:S  pas
3  -3:S  pas
4  -4:S  pas
5  -5:S  pas
6  -6:S  pas
7  -7:S  pas
8  -8:S  pas
9  -9:S  pas
10  -10:S  pas
11  -11:S  pas
12  -12:S  pas
13  -13:S  pas
14  -14:S  pas
15  -15:S  pas
16  -16:S  pas
17  -17:S  pas
18  -18:S  pas
19  -19:S  pas
20  -20:S  pas
21  -21:S  pas

## Footprint 52745-2190 (pad centres in mm)
FFC/FPC-to-Board 0.50mm (.020") SMT Top Contact Right Angle, ZIF, Style Receptacle 52745 / 52435 Source: http://www.molex.com/product/ffc/52745.html
smd 0.3 x 0.8: 1 -5,2.5; 2 -4.5,2.5; 3 -4,2.5; 4 -3.5,2.5; 5 -3,2.5; 6 -2.5,2.5; 7 -2,2.5; 8 -1.5,2.5; 9 -1,2.5; 10 -0.5,2.5; 11 0,2.5; 12 0.5,2.5; 13 1,2.5; 14 1.5,2.5; 15 2,2.5; 16 2.5,2.5; 17 3,2.5; 18 3.5,2.5; 19 4,2.5; 20 4.5,2.5; 21 5,2.5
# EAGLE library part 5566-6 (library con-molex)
Mini FIT connector 6 pol Source: http://www.molex.com

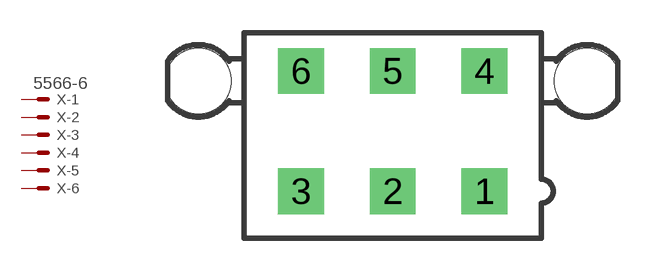
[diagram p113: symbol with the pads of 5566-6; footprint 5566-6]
Designator prefix X; gates -1=MV -2=M -3=M -4=M -5=M -6=M

## 5566-6 (MPN: 95566-61002; OC_FARNELL: unknown; OC_NEWARK: 22K8620)  [5566-6]
1  -1:S  pas
2  -2:S  pas
3  -3:S  pas
4  -4:S  pas
5  -5:S  pas
6  -6:S  pas

## Footprint 5566-6 (pad centres in mm)
Mini FIT connector 6 pol Source: http://www.molex.com
drill 1.4 square: 1 4.2,-2.75; 2 0,-2.75; 3 -4.2,-2.75; 4 4.2,2.75; 5 0,2.75; 6 -4.2,2.75
hole 3 at 8.9,2.29
hole 3 at -8.9,2.29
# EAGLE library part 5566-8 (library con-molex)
Mini FIT connector 8 pol Source: http://www.molex.com

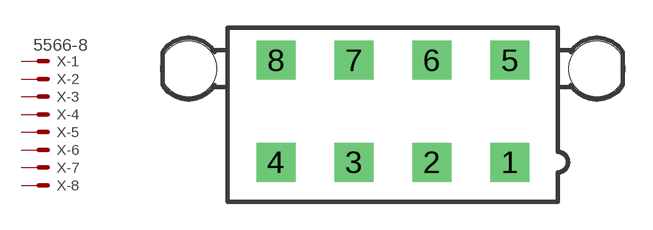
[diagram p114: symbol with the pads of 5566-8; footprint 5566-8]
Designator prefix X; gates -1=MV -2=M -3=M -4=M -5=M -6=M -7=M -8=M

## 5566-8 (OC_FARNELL: unknown; OC_NEWARK: unknown)  [5566-8]
1  -1:S  pas
2  -2:S  pas
3  -3:S  pas
4  -4:S  pas
5  -5:S  pas
6  -6:S  pas
7  -7:S  pas
8  -8:S  pas

## Footprint 5566-8 (pad centres in mm)
Mini FIT connector 8 pol Source: http://www.molex.com
drill 1.4 square: 1 6.3,-2.75; 2 2.1,-2.75; 3 -2.1,-2.75; 4 -6.3,-2.75; 5 6.3,2.75; 6 2.1,2.75; 7 -2.1,2.75; 8 -6.3,2.75
hole 3 at 11,2.29
hole 3 at -11,2.29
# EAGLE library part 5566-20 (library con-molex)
Mini FIT connector 20 pol ATX PC-Motherboard Power connector Source: http://www.molex.com

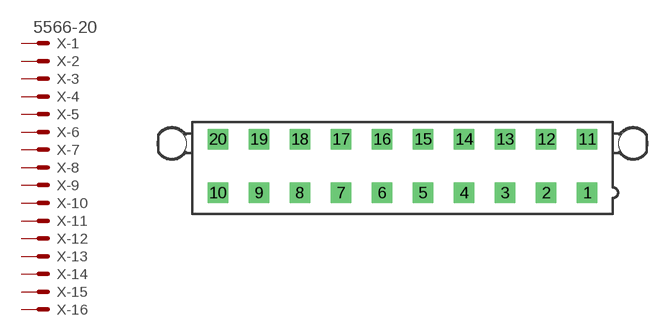
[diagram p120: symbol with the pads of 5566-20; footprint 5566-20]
Designator prefix X; gates -1=MV -2=M -3=M -4=M -5=M -6=M -7=M -8=M -9=M -10=M -11=M -12=M -13=M -14=M -15=M -16=M -17=M -18=M -19=M -20=M

## 5566-20 (OC_FARNELL: unknown; OC_NEWARK: unknown)  [5566-20]
1  -1:S  pas
2  -2:S  pas
3  -3:S  pas
4  -4:S  pas
5  -5:S  pas
6  -6:S  pas
7  -7:S  pas
8  -8:S  pas
9  -9:S  pas
10  -10:S  pas
11  -11:S  pas
12  -12:S  pas
13  -13:S  pas
14  -14:S  pas
15  -15:S  pas
16  -16:S  pas
17  -17:S  pas
18  -18:S  pas
19  -19:S  pas
20  -20:S  pas

## Footprint 5566-20 (pad centres in mm)
Mini FIT connector 20 pol ATX PC-Motherboard Power connector Source: http://www.molex.com
drill 1.4 square: 1 18.9,-2.75; 2 14.7,-2.75; 3 10.5,-2.75; 4 6.3,-2.75; 5 2.1,-2.75; 6 -2.1,-2.75; 7 -6.3,-2.75; 8 -10.5,-2.75; 9 -14.7,-2.75; 10 -18.9,-2.75; 11 18.9,2.75; 12 14.7,2.75; 13 10.5,2.75; 14 6.3,2.75; 15 2.1,2.75; 16 -2.1,2.75; 17 -6.3,2.75; 18 -10.5,2.75; 19 -14.7,2.75; 20 -18.9,2.75
hole 3 at 23.6,2.29
hole 3 at -23.6,2.29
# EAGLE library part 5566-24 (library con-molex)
Mini FIT connector 24 pol Source: http://www.molex.com

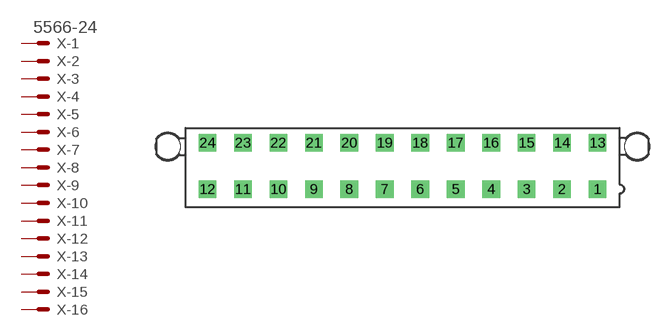
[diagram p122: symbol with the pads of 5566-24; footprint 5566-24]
Designator prefix X; gates -1=MV -2=M -3=M -4=M -5=M -6=M -7=M -8=M -9=M -10=M -11=M -12=M -13=M -14=M -15=M -16=M -17=M -18=M -19=M -20=M -21=M -22=M -23=M -24=M

## 5566-24 (OC_FARNELL: unknown; OC_NEWARK: unknown)  [5566-24]
1  -1:S  pas
2  -2:S  pas
3  -3:S  pas
4  -4:S  pas
5  -5:S  pas
6  -6:S  pas
7  -7:S  pas
8  -8:S  pas
9  -9:S  pas
10  -10:S  pas
11  -11:S  pas
12  -12:S  pas
13  -13:S  pas
14  -14:S  pas
15  -15:S  pas
16  -16:S  pas
17  -17:S  pas
18  -18:S  pas
19  -19:S  pas
20  -20:S  pas
21  -21:S  pas
22  -22:S  pas
23  -23:S  pas
24  -24:S  pas

## Footprint 5566-24 (pad centres in mm)
Mini FIT connector 24 pol Source: http://www.molex.com
drill 1.4 square: 1 23.1,-2.75; 2 18.9,-2.75; 3 14.7,-2.75; 4 10.5,-2.75; 5 6.3,-2.75; 6 2.1,-2.75; 7 -2.1,-2.75; 8 -6.3,-2.75; 9 -10.5,-2.75; 10 -14.7,-2.75; 11 -18.9,-2.75; 12 -23.1,-2.75; 13 23.1,2.75; 14 18.9,2.75; 15 14.7,2.75; 16 10.5,2.75; 17 6.3,2.75; 18 2.1,2.75; 19 -2.1,2.75; 20 -6.3,2.75; 21 -10.5,2.75; 22 -14.7,2.75; 23 -18.9,2.75; 24 -23.1,2.75
hole 3 at 27.8,2.29
hole 3 at -27.8,2.29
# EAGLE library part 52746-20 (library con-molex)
FPC Connector ZIF for SMT 0.5mm Source: http://www.farnell.com/datasheets/73044.pdf [DWG. NO. (Sheet 1 OF 2) SD-52746-**17] Distributor: Farnell 9786350

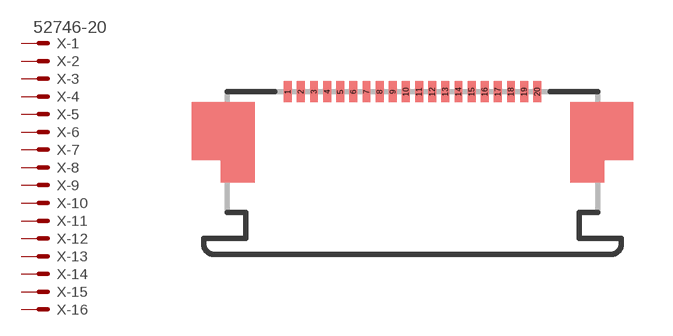
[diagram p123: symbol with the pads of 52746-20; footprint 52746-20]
Designator prefix X; gates -1=MV -2=M -3=M -4=M -5=M -6=M -7=M -8=M -9=M -10=M -11=M -12=M -13=M -14=M -15=M -16=M -17=M -18=M -19=M -20=M

## 52746-20 (OC_FARNELL: 9786350; OC_NEWARK: unknown)  [52746-20]
1  -1:S  pas
2  -2:S  pas
3  -3:S  pas
4  -4:S  pas
5  -5:S  pas
6  -6:S  pas
7  -7:S  pas
8  -8:S  pas
9  -9:S  pas
10  -10:S  pas
11  -11:S  pas
12  -12:S  pas
13  -13:S  pas
14  -14:S  pas
15  -15:S  pas
16  -16:S  pas
17  -17:S  pas
18  -18:S  pas
19  -19:S  pas
20  -20:S  pas

## Footprint 52746-20 (pad centres in mm)
FPC Connector ZIF for SMT 0.5mm Source: http://www.farnell.com/datasheets/73044.pdf [DWG. NO. (Sheet 1 OF 2) SD-52746-**17] Distributor: Farnell 9786350
smd 0.3 x 0.8: 1 -4.75,0.6; 2 -4.25,0.6; 3 -3.75,0.6; 4 -3.25,0.6; 5 -2.75,0.6; 6 -2.25,0.6; 7 -1.75,0.6; 8 -1.25,0.6; 9 -0.75,0.6; 10 -0.25,0.6; 11 0.25,0.6; 12 0.75,0.6; 13 1.25,0.6; 14 1.75,0.6; 15 2.25,0.6; 16 2.75,0.6; 17 3.25,0.6; 18 3.75,0.6; 19 4.25,0.6; 20 4.75,0.6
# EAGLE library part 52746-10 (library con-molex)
FPC Connector ZIF for SMT 0.5mm Source: http://www.farnell.com/datasheets/73044.pdf [DWG. NO. (Sheet 1 OF 2) SD-52746-**17]

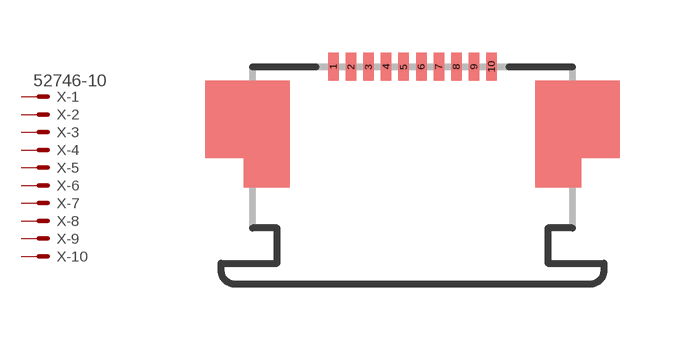
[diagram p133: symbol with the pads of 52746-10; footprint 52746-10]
Designator prefix X; gates -1=MV -2=M -3=M -4=M -5=M -6=M -7=M -8=M -9=M -10=M

## 52746-10 (OC_FARNELL: 1827154; OC_NEWARK: unknown)  [52746-10]
1  -1:S  pas
2  -2:S  pas
3  -3:S  pas
4  -4:S  pas
5  -5:S  pas
6  -6:S  pas
7  -7:S  pas
8  -8:S  pas
9  -9:S  pas
10  -10:S  pas

## Footprint 52746-10 (pad centres in mm)
FPC Connector ZIF for SMT 0.5mm Source: http://www.farnell.com/datasheets/73044.pdf [DWG. NO. (Sheet 1 OF 2) SD-52746-**17]
smd 0.3 x 0.8: 1 -2.25,0.6; 2 -1.75,0.6; 3 -1.25,0.6; 4 -0.75,0.6; 5 -0.25,0.6; 6 0.25,0.6; 7 0.75,0.6; 8 1.25,0.6; 9 1.75,0.6; 10 2.25,0.6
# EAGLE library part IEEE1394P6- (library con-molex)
IEEE 1394 6P Connector Source: http://www.molex.com/pdm_docs/sd/534620621_sd.pdf

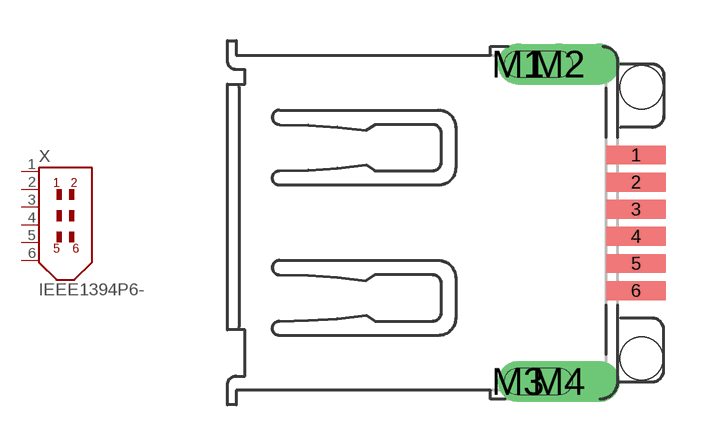
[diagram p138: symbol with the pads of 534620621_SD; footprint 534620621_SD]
Designator prefix X

## IEEE1394P6-534620621 (OC_FARNELL: unknown; OC_NEWARK: unknown)  [534620621_SD]
1  1  pas
2  2  pas
3  3  pas
4  4  pas
5  5  pas
6  6  pas

## Footprint 534620621_SD (pad centres in mm)
IEEE 1394 2.0 I/O Conn. Socket Right-Angle Flat with Kink Source: http://www.molex.com/pdm_docs/sd/534620621_sd.pdf
smd 2.2 x 0.7: 1 8.25,2.5; 2 8.25,1.5; 3 8.25,0.5; 4 8.25,-0.5; 5 8.25,-1.5; 6 8.25,-2.5
drill 1 pad 1.27 offset: M1 3.9,5.85; M2 5.4,5.85; M3 3.9,-5.85; M4 5.4,-5.85
hole 1.6 at 8.45,5
hole 1.6 at 8.45,-5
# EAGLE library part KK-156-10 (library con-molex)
KK 156 HEADER Source: http://www.molex.com/pdm_docs/sd/026604100_sd.pdf

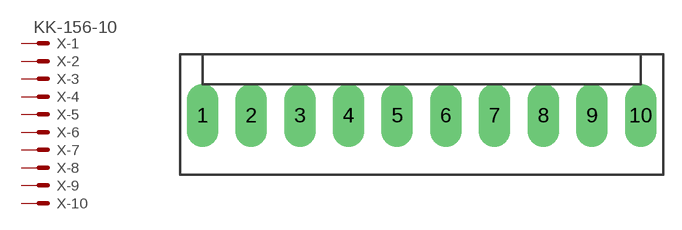
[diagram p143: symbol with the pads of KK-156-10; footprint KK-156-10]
Designator prefix X; gates -1=MV -2=M -3=M -4=M -5=M -6=M -7=M -8=M -9=M -10=M

## KK-156-10 (OC_FARNELL: unknown; OC_NEWARK: unknown)  [KK-156-10]
1  -1:S  pas
2  -2:S  pas
3  -3:S  pas
4  -4:S  pas
5  -5:S  pas
6  -6:S  pas
7  -7:S  pas
8  -8:S  pas
9  -9:S  pas
10  -10:S  pas

## Footprint KK-156-10 (pad centres in mm)
KK 156 HEADER Source: http://www.molex.com/pdm_docs/sd/026604100_sd.pdf
drill 1.7 pad 2.184 long: 1 -17.82,0; 2 -13.86,0; 3 -9.9,0; 4 -5.94,0; 5 -1.98,0; 6 1.98,0; 7 5.94,0; 8 9.9,0; 9 13.86,0; 10 17.82,0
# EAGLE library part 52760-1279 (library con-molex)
MOLEX Connector SD-52760-**79 Source: 52760-1079_sd molex.pdf

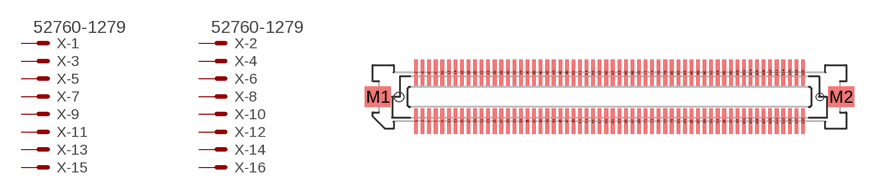
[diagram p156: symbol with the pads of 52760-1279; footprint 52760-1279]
Designator prefix X; gates -1=MV -2=MV -3=M -4=M -5=M -6=M -7=M -8=M -9=M -10=M -11=M -12=M -13=M -14=M -15=M -16=M -17=M -18=M -19=M -20=M -21=M -22=M -23=M -24=M -25=M -26=M -27=M -28=M -29=M -30=M -31=M -32=M -33=M -34=M -35=M -36=M -37=M -38=M -39=M -40=M -41=M -42=M -43=M -44=M -45=M -46=M -47=M -48=M -49=M -50=M -51=M -52=M -53=M -54=M -55=M -56=M -57=M -58=M -59=M -60=M -61=M -62=M -63=M -64=M -65=M -66=M -67=M -68=M -69=M -70=M -71=M -72=M -73=M -74=M -75=M -76=M -77=M -78=M -79=M -80=M -81=M -82=M -83=M -84=M -85=M -86=M -87=M -88=M -89=M -90=M -91=M -92=M -93=M -94=M -95=M -96=M -97=M -98=M -99=M -100=M -101=M -102=M -103=M -104=M -105=M -106=M -107=M -108=M -109=M -110=M -111=M -112=M -113=M -114=M -115=M -116=M -117=M -118=M -119=M -120=M

## 52760-1279 (OC_FARNELL: unknown; OC_NEWARK: unknown)  [52760-1279]
1  -1:S  pas
2  -2:S  pas
3  -3:S  pas
4  -4:S  pas
5  -5:S  pas
6  -6:S  pas
7  -7:S  pas
8  -8:S  pas
9  -9:S  pas
10  -10:S  pas
11  -11:S  pas
12  -12:S  pas
13  -13:S  pas
14  -14:S  pas
15  -15:S  pas
16  -16:S  pas
17  -17:S  pas
18  -18:S  pas
19  -19:S  pas
20  -20:S  pas
21  -21:S  pas
22  -22:S  pas
23  -23:S  pas
24  -24:S  pas
25  -25:S  pas
26  -26:S  pas
27  -27:S  pas
28  -28:S  pas
29  -29:S  pas
30  -30:S  pas
31  -31:S  pas
32  -32:S  pas
33  -33:S  pas
34  -34:S  pas
35  -35:S  pas
36  -36:S  pas
37  -37:S  pas
38  -38:S  pas
39  -39:S  pas
40  -40:S  pas
41  -41:S  pas
42  -42:S  pas
43  -43:S  pas
44  -44:S  pas
45  -45:S  pas
46  -46:S  pas
47  -47:S  pas
48  -48:S  pas
49  -49:S  pas
50  -50:S  pas
51  -51:S  pas
52  -52:S  pas
53  -53:S  pas
54  -54:S  pas
55  -55:S  pas
56  -56:S  pas
57  -57:S  pas
58  -58:S  pas
59  -59:S  pas
60  -60:S  pas
61  -61:S  pas
62  -62:S  pas
63  -63:S  pas
64  -64:S  pas
65  -65:S  pas
66  -66:S  pas
67  -67:S  pas
68  -68:S  pas
69  -69:S  pas
70  -70:S  pas
71  -71:S  pas
72  -72:S  pas
73  -73:S  pas
74  -74:S  pas
75  -75:S  pas
76  -76:S  pas
77  -77:S  pas
78  -78:S  pas
79  -79:S  pas
80  -80:S  pas
81  -81:S  pas
82  -82:S  pas
83  -83:S  pas
84  -84:S  pas
85  -85:S  pas
86  -86:S  pas
87  -87:S  pas
88  -88:S  pas
89  -89:S  pas
90  -90:S  pas
91  -91:S  pas
92  -92:S  pas
93  -93:S  pas
94  -94:S  pas
95  -95:S  pas
96  -96:S  pas
97  -97:S  pas
98  -98:S  pas
99  -99:S  pas
100  -100:S  pas
101  -101:S  pas
102  -102:S  pas
103  -103:S  pas
104  -104:S  pas
105  -105:S  pas
106  -106:S  pas
107  -107:S  pas
108  -108:S  pas
109  -109:S  pas
110  -110:S  pas
111  -111:S  pas
112  -112:S  pas
113  -113:S  pas
114  -114:S  pas
115  -115:S  pas
116  -116:S  pas
117  -117:S  pas
118  -118:S  pas
119  -119:S  pas
120  -120:S  pas

## Footprint 52760-1279 (pad centres in mm)
MOLEX Connector SD-52760-**79 Source: 52760-1079_sd molex.pdf
smd 0.35 x 2.5: 1 -18.733,-2.35; 2 -18.733,2.35; 3 -18.098,-2.35; 4 -18.098,2.35; 5 -17.462,-2.35; 6 -17.462,2.35; 7 -16.828,-2.35; 8 -16.828,2.35; 9 -16.192,-2.35; 10 -16.192,2.35; 11 -15.557,-2.35; 12 -15.557,2.35; 13 -14.922,-2.35; 14 -14.922,2.35; 15 -14.287,-2.35; 16 -14.287,2.35; 17 -13.652,-2.35; 18 -13.652,2.35; 19 -13.018,-2.35; 20 -13.018,2.35; 21 -12.383,-2.35; 22 -12.383,2.35; 23 -11.748,-2.35; 24 -11.748,2.35; 25 -11.113,-2.35; 26 -11.113,2.35; 27 -10.477,-2.35; 28 -10.477,2.35; 29 -9.842,-2.35; 30 -9.842,2.35; 31 -9.207,-2.35; 32 -9.207,2.35; 33 -8.572,-2.35; 34 -8.572,2.35; 35 -7.938,-2.35; 36 -7.938,2.35; 37 -7.303,-2.35; 38 -7.303,2.35; 39 -6.668,-2.35; 40 -6.668,2.35; 41 -6.032,-2.35; 42 -6.032,2.35; 43 -5.397,-2.35; 44 -5.397,2.35; 45 -4.763,-2.35; 46 -4.763,2.35; 47 -4.128,-2.35; 48 -4.128,2.35; 49 -3.493,-2.35; 50 -3.493,2.35; 51 -2.857,-2.35; 52 -2.857,2.35; 53 -2.223,-2.35; 54 -2.223,2.35; 55 -1.587,-2.35; 56 -1.587,2.35; 57 -0.953,-2.35; 58 -0.953,2.35; 59 -0.318,-2.35; 60 -0.318,2.35; 61 0.318,-2.35; 62 0.318,2.35; 63 0.953,-2.35; 64 0.953,2.35; 65 1.587,-2.35; 66 1.587,2.35; 67 2.223,-2.35; 68 2.223,2.35; 69 2.857,-2.35; 70 2.857,2.35; 71 3.493,-2.35; 72 3.493,2.35; 73 4.128,-2.35; 74 4.128,2.35; 75 4.763,-2.35; 76 4.763,2.35; 77 5.397,-2.35; 78 5.397,2.35; 79 6.032,-2.35; 80 6.032,2.35; 81 6.668,-2.35; 82 6.668,2.35; 83 7.303,-2.35; 84 7.303,2.35; 85 7.938,-2.35; 86 7.938,2.35; 87 8.572,-2.35; 88 8.572,2.35; 89 9.207,-2.35; 90 9.207,2.35; 91 9.842,-2.35; 92 9.842,2.35; 93 10.477,-2.35; 94 10.477,2.35; 95 11.113,-2.35; 96 11.113,2.35; 97 11.748,-2.35; 98 11.748,2.35; 99 12.383,-2.35; 100 12.383,2.35; 101 13.018,-2.35; 102 13.018,2.35; 103 13.652,-2.35; 104 13.652,2.35; 105 14.287,-2.35; 106 14.287,2.35; 107 14.922,-2.35; 108 14.922,2.35; 109 15.557,-2.35; 110 15.557,2.35; 111 16.192,-2.35; 112 16.192,2.35; 113 16.828,-2.35; 114 16.828,2.35; 115 17.462,-2.35; 116 17.462,2.35; 117 18.098,-2.35; 118 18.098,2.35; 119 18.733,-2.35; 120 18.733,2.35
smd 2.5 x 2: M1 -22.425,0; M2 22.425,0
hole 0.9 at -20.385,0
hole 0.7 at 20.385,0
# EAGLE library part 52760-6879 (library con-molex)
MOLEX Connector SD-52760-**79 Source: 52760-1079_sd molex.pdf

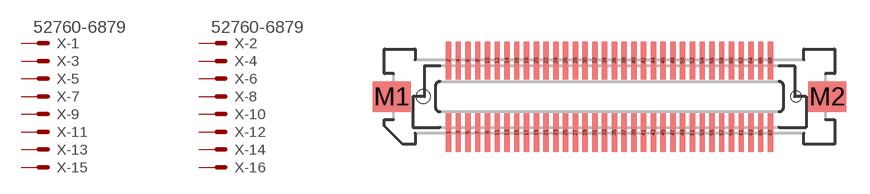
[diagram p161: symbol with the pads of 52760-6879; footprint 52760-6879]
Designator prefix X; gates -1=MV -2=MV -3=M -4=M -5=M -6=M -7=M -8=M -9=M -10=M -11=M -12=M -13=M -14=M -15=M -16=M -17=M -18=M -19=M -20=M -21=M -22=M -23=M -24=M -25=M -26=M -27=M -28=M -29=M -30=M -31=M -32=M -33=M -34=M -35=M -36=M -37=M -38=M -39=M -40=M -41=M -42=M -43=M -44=M -45=M -46=M -47=M -48=M -49=M -50=M -51=M -52=M -53=M -54=M -55=M -56=M -57=M -58=M -59=M -60=M -61=M -62=M -63=M -64=M -65=M -66=M -67=M -68=M

## 52760-6879 (OC_FARNELL: unknown; OC_NEWARK: unknown)  [52760-6879]
1  -1:S  pas
2  -2:S  pas
3  -3:S  pas
4  -4:S  pas
5  -5:S  pas
6  -6:S  pas
7  -7:S  pas
8  -8:S  pas
9  -9:S  pas
10  -10:S  pas
11  -11:S  pas
12  -12:S  pas
13  -13:S  pas
14  -14:S  pas
15  -15:S  pas
16  -16:S  pas
17  -17:S  pas
18  -18:S  pas
19  -19:S  pas
20  -20:S  pas
21  -21:S  pas
22  -22:S  pas
23  -23:S  pas
24  -24:S  pas
25  -25:S  pas
26  -26:S  pas
27  -27:S  pas
28  -28:S  pas
29  -29:S  pas
30  -30:S  pas
31  -31:S  pas
32  -32:S  pas
33  -33:S  pas
34  -34:S  pas
35  -35:S  pas
36  -36:S  pas
37  -37:S  pas
38  -38:S  pas
39  -39:S  pas
40  -40:S  pas
41  -41:S  pas
42  -42:S  pas
43  -43:S  pas
44  -44:S  pas
45  -45:S  pas
46  -46:S  pas
47  -47:S  pas
48  -48:S  pas
49  -49:S  pas
50  -50:S  pas
51  -51:S  pas
52  -52:S  pas
53  -53:S  pas
54  -54:S  pas
55  -55:S  pas
56  -56:S  pas
57  -57:S  pas
58  -58:S  pas
59  -59:S  pas
60  -60:S  pas
61  -61:S  pas
62  -62:S  pas
63  -63:S  pas
64  -64:S  pas
65  -65:S  pas
66  -66:S  pas
67  -67:S  pas
68  -68:S  pas

## Footprint 52760-6879 (pad centres in mm)
MOLEX Connector SD-52760-**79 Source: 52760-1079_sd molex.pdf
smd 0.35 x 2.5: 1 -10.477,-2.35; 2 -10.477,2.35; 3 -9.842,-2.35; 4 -9.842,2.35; 5 -9.207,-2.35; 6 -9.207,2.35; 7 -8.572,-2.35; 8 -8.572,2.35; 9 -7.938,-2.35; 10 -7.938,2.35; 11 -7.303,-2.35; 12 -7.303,2.35; 13 -6.668,-2.35; 14 -6.668,2.35; 15 -6.032,-2.35; 16 -6.032,2.35; 17 -5.397,-2.35; 18 -5.397,2.35; 19 -4.763,-2.35; 20 -4.763,2.35; 21 -4.128,-2.35; 22 -4.128,2.35; 23 -3.493,-2.35; 24 -3.493,2.35; 25 -2.857,-2.35; 26 -2.857,2.35; 27 -2.223,-2.35; 28 -2.223,2.35; 29 -1.587,-2.35; 30 -1.587,2.35; 31 -0.953,-2.35; 32 -0.953,2.35; 33 -0.318,-2.35; 34 -0.318,2.35; 35 0.318,-2.35; 36 0.318,2.35; 37 0.953,-2.35; 38 0.953,2.35; 39 1.587,-2.35; 40 1.587,2.35; 41 2.223,-2.35; 42 2.223,2.35; 43 2.857,-2.35; 44 2.857,2.35; 45 3.493,-2.35; 46 3.493,2.35; 47 4.128,-2.35; 48 4.128,2.35; 49 4.763,-2.35; 50 4.763,2.35; 51 5.397,-2.35; 52 5.397,2.35; 53 6.032,-2.35; 54 6.032,2.35; 55 6.668,-2.35; 56 6.668,2.35; 57 7.303,-2.35; 58 7.303,2.35; 59 7.938,-2.35; 60 7.938,2.35; 61 8.572,-2.35; 62 8.572,2.35; 63 9.207,-2.35; 64 9.207,2.35; 65 9.842,-2.35; 66 9.842,2.35; 67 10.477,-2.35; 68 10.477,2.35
smd 2.5 x 2: M1 -14.17,0; M2 14.17,0
hole 0.9 at -12.13,0
hole 0.7 at 12.13,0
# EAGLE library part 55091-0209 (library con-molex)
0.635 mm PITCH B TO B CONN. Source: http://www.molex.com/pdm_docs/sd/550911609_sd.pdf

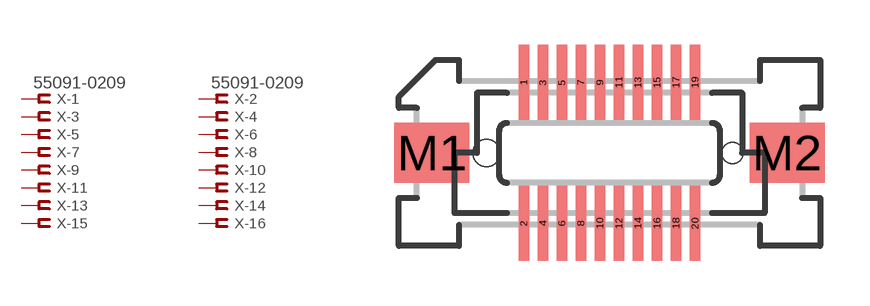
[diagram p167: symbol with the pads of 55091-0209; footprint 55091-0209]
Designator prefix X; gates -1=FV -2=FV -3=F -4=F -5=F -6=F -7=F -8=F -9=F -10=F -11=F -12=F -13=F -14=F -15=F -16=F -17=F -18=F -19=F -20=F

## 55091-0209 (OC_FARNELL: unknown; OC_NEWARK: unknown)  [55091-0209]
1  -1:S  pas
2  -2:S  pas
3  -3:S  pas
4  -4:S  pas
5  -5:S  pas
6  -6:S  pas
7  -7:S  pas
8  -8:S  pas
9  -9:S  pas
10  -10:S  pas
11  -11:S  pas
12  -12:S  pas
13  -13:S  pas
14  -14:S  pas
15  -15:S  pas
16  -16:S  pas
17  -17:S  pas
18  -18:S  pas
19  -19:S  pas
20  -20:S  pas

## Footprint 55091-0209 (pad centres in mm)
0.635 mm PITCH B TO B CONN. Source: http://www.molex.com/pdm_docs/sd/550911609_sd.pdf
smd 0.35 x 2.5: 1 -2.857,2.35; 2 -2.857,-2.35; 3 -2.223,2.35; 4 -2.223,-2.35; 5 -1.587,2.35; 6 -1.587,-2.35; 7 -0.953,2.35; 8 -0.953,-2.35; 9 -0.318,2.35; 10 -0.318,-2.35; 11 0.318,2.35; 12 0.318,-2.35; 13 0.953,2.35; 14 0.953,-2.35; 15 1.587,2.35; 16 1.587,-2.35; 17 2.223,2.35; 18 2.223,-2.35; 19 2.857,2.35; 20 2.857,-2.35
smd 2.5 x 2: M1 -5.925,0; M2 5.925,0
hole 0.9 at -4.11,0
hole 0.7 at 4.11,0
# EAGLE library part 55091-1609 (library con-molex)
0.635 mm PITCH B TO B CONN. Source: http://www.molex.com/pdm_docs/sd/550911609_sd.pdf

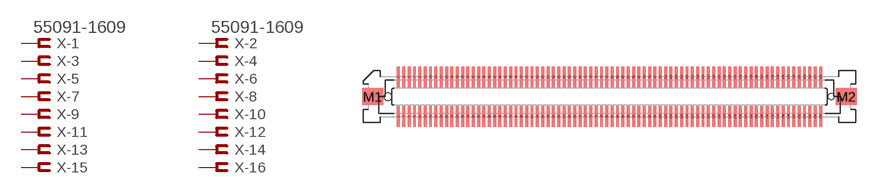
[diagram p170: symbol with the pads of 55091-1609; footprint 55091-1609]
Designator prefix X; gates -1=FV -2=FV -3=F -4=F -5=F -6=F -7=F -8=F -9=F -10=F -11=F -12=F -13=F -14=F -15=F -16=F -17=F -18=F -19=F -20=F -21=F -22=F -23=F -24=F -25=F -26=F -27=F -28=F -29=F -30=F -31=F -32=F -33=F -34=F -35=F -36=F -37=F -38=F -39=F -40=F -41=F -42=F -43=F -44=F -45=F -46=F -47=F -48=F -49=F -50=F -51=F -52=F -53=F -54=F -55=F -56=F -57=F -58=F -59=F -60=F -61=F -62=F -63=F -64=F -65=F -66=F -67=F -68=F -69=F -70=F -71=F -72=F -73=F -74=F -75=F -76=F -77=F -78=F -79=F -80=F -81=F -82=F -83=F -84=F -85=F -86=F -87=F -88=F -89=F -90=F -91=F -92=F -93=F -94=F -95=F -96=F -97=F -98=F -99=F -100=F -101=F -102=F -103=F -104=F -105=F -106=F -107=F -108=F -109=F -110=F -111=F -112=F -113=F -114=F -115=F -116=F -117=F -118=F -119=F -120=F -121=F -122=F -123=F -124=F -125=F -126=F -127=F -128=F -129=F -130=F -131=F -132=F -133=F -134=F -135=F -136=F -137=F -138=F -139=F -140=F -141=F -142=F -143=F -144=F -145=F -146=F -147=F -148=F -149=F -150=F -151=F -152=F -153=F -154=F -155=F -156=F -157=F -158=F -159=F -160=F

## 55091-1609 (OC_FARNELL: unknown; OC_NEWARK: unknown)  [55091-1609]
1  -1:S  pas
2  -2:S  pas
3  -3:S  pas
4  -4:S  pas
5  -5:S  pas
6  -6:S  pas
7  -7:S  pas
8  -8:S  pas
9  -9:S  pas
10  -10:S  pas
11  -11:S  pas
12  -12:S  pas
13  -13:S  pas
14  -14:S  pas
15  -15:S  pas
16  -16:S  pas
17  -17:S  pas
18  -18:S  pas
19  -19:S  pas
20  -20:S  pas
21  -21:S  pas
22  -22:S  pas
23  -23:S  pas
24  -24:S  pas
25  -25:S  pas
26  -26:S  pas
27  -27:S  pas
28  -28:S  pas
29  -29:S  pas
30  -30:S  pas
31  -31:S  pas
32  -32:S  pas
33  -33:S  pas
34  -34:S  pas
35  -35:S  pas
36  -36:S  pas
37  -37:S  pas
38  -38:S  pas
39  -39:S  pas
40  -40:S  pas
41  -41:S  pas
42  -42:S  pas
43  -43:S  pas
44  -44:S  pas
45  -45:S  pas
46  -46:S  pas
47  -47:S  pas
48  -48:S  pas
49  -49:S  pas
50  -50:S  pas
51  -51:S  pas
52  -52:S  pas
53  -53:S  pas
54  -54:S  pas
55  -55:S  pas
56  -56:S  pas
57  -57:S  pas
58  -58:S  pas
59  -59:S  pas
60  -60:S  pas
61  -61:S  pas
62  -62:S  pas
63  -63:S  pas
64  -64:S  pas
65  -65:S  pas
66  -66:S  pas
67  -67:S  pas
68  -68:S  pas
69  -69:S  pas
70  -70:S  pas
71  -71:S  pas
72  -72:S  pas
73  -73:S  pas
74  -74:S  pas
75  -75:S  pas
76  -76:S  pas
77  -77:S  pas
78  -78:S  pas
79  -79:S  pas
80  -80:S  pas
81  -81:S  pas
82  -82:S  pas
83  -83:S  pas
84  -84:S  pas
85  -85:S  pas
86  -86:S  pas
87  -87:S  pas
88  -88:S  pas
89  -89:S  pas
90  -90:S  pas
91  -91:S  pas
92  -92:S  pas
93  -93:S  pas
94  -94:S  pas
95  -95:S  pas
96  -96:S  pas
97  -97:S  pas
98  -98:S  pas
99  -99:S  pas
100  -100:S  pas
101  -101:S  pas
102  -102:S  pas
103  -103:S  pas
104  -104:S  pas
105  -105:S  pas
106  -106:S  pas
107  -107:S  pas
108  -108:S  pas
109  -109:S  pas
110  -110:S  pas
111  -111:S  pas
112  -112:S  pas
113  -113:S  pas
114  -114:S  pas
115  -115:S  pas
116  -116:S  pas
117  -117:S  pas
118  -118:S  pas
119  -119:S  pas
120  -120:S  pas
121  -121:S  pas
122  -122:S  pas
123  -123:S  pas
124  -124:S  pas
125  -125:S  pas
126  -126:S  pas
127  -127:S  pas
128  -128:S  pas
129  -129:S  pas
130  -130:S  pas
131  -131:S  pas
132  -132:S  pas
133  -133:S  pas
134  -134:S  pas
135  -135:S  pas
136  -136:S  pas
137  -137:S  pas
138  -138:S  pas
139  -139:S  pas
140  -140:S  pas
141  -141:S  pas
142  -142:S  pas
143  -143:S  pas
144  -144:S  pas
145  -145:S  pas
146  -146:S  pas
147  -147:S  pas
148  -148:S  pas
149  -149:S  pas
150  -150:S  pas
151  -151:S  pas
152  -152:S  pas
153  -153:S  pas
154  -154:S  pas
155  -155:S  pas
156  -156:S  pas
157  -157:S  pas
158  -158:S  pas
159  -159:S  pas
160  -160:S  pas

## Footprint 55091-1609 (pad centres in mm)
0.635 mm PITCH B TO B CONN. Source: http://www.molex.com/pdm_docs/sd/550911609_sd.pdf
smd 0.35 x 2.5: 1 -25.082,2.35; 2 -25.082,-2.35; 3 -24.448,2.35; 4 -24.448,-2.35; 5 -23.812,2.35; 6 -23.812,-2.35; 7 -23.177,2.35; 8 -23.177,-2.35; 9 -22.543,2.35; 10 -22.543,-2.35; 11 -21.907,2.35; 12 -21.907,-2.35; 13 -21.273,2.35; 14 -21.273,-2.35; 15 -20.637,2.35; 16 -20.637,-2.35; 17 -20.003,2.35; 18 -20.003,-2.35; 19 -19.367,2.35; 20 -19.367,-2.35; 21 -18.733,2.35; 22 -18.733,-2.35; 23 -18.098,2.35; 24 -18.098,-2.35; 25 -17.462,2.35; 26 -17.462,-2.35; 27 -16.828,2.35; 28 -16.828,-2.35; 29 -16.192,2.35; 30 -16.192,-2.35; 31 -15.557,2.35; 32 -15.557,-2.35; 33 -14.922,2.35; 34 -14.922,-2.35; 35 -14.287,2.35; 36 -14.287,-2.35; 37 -13.652,2.35; 38 -13.652,-2.35; 39 -13.018,2.35; 40 -13.018,-2.35; 41 -12.383,2.35; 42 -12.383,-2.35; 43 -11.748,2.35; 44 -11.748,-2.35; 45 -11.113,2.35; 46 -11.113,-2.35; 47 -10.477,2.35; 48 -10.477,-2.35; 49 -9.842,2.35; 50 -9.842,-2.35; 51 -9.207,2.35; 52 -9.207,-2.35; 53 -8.572,2.35; 54 -8.572,-2.35; 55 -7.938,2.35; 56 -7.938,-2.35; 57 -7.303,2.35; 58 -7.303,-2.35; 59 -6.668,2.35; 60 -6.668,-2.35; 61 -6.032,2.35; 62 -6.032,-2.35; 63 -5.397,2.35; 64 -5.397,-2.35; 65 -4.763,2.35; 66 -4.763,-2.35; 67 -4.128,2.35; 68 -4.128,-2.35; 69 -3.493,2.35; 70 -3.493,-2.35; 71 -2.857,2.35; 72 -2.857,-2.35; 73 -2.223,2.35; 74 -2.223,-2.35; 75 -1.587,2.35; 76 -1.587,-2.35; 77 -0.953,2.35; 78 -0.953,-2.35; 79 -0.318,2.35; 80 -0.318,-2.35; 81 0.318,2.35; 82 0.318,-2.35; 83 0.953,2.35; 84 0.953,-2.35; 85 1.587,2.35; 86 1.587,-2.35; 87 2.223,2.35; 88 2.223,-2.35; 89 2.857,2.35; 90 2.857,-2.35; 91 3.493,2.35; 92 3.493,-2.35; 93 4.128,2.35; 94 4.128,-2.35; 95 4.763,2.35; 96 4.763,-2.35; 97 5.397,2.35; 98 5.397,-2.35; 99 6.032,2.35; 100 6.032,-2.35; 101 6.668,2.35; 102 6.668,-2.35; 103 7.303,2.35; 104 7.303,-2.35; 105 7.938,2.35; 106 7.938,-2.35; 107 8.572,2.35; 108 8.572,-2.35; 109 9.207,2.35; 110 9.207,-2.35; 111 9.842,2.35; 112 9.842,-2.35; 113 10.477,2.35; 114 10.477,-2.35; 115 11.113,2.35; 116 11.113,-2.35; 117 11.748,2.35; 118 11.748,-2.35; 119 12.383,2.35; 120 12.383,-2.35; 121 13.018,2.35; 122 13.018,-2.35; 123 13.652,2.35; 124 13.652,-2.35; 125 14.287,2.35; 126 14.287,-2.35; 127 14.922,2.35; 128 14.922,-2.35; 129 15.557,2.35; 130 15.557,-2.35; 131 16.192,2.35; 132 16.192,-2.35; 133 16.828,2.35; 134 16.828,-2.35; 135 17.462,2.35; 136 17.462,-2.35; 137 18.098,2.35; 138 18.098,-2.35; 139 18.733,2.35; 140 18.733,-2.35; 141 19.367,2.35; 142 19.367,-2.35; 143 20.003,2.35; 144 20.003,-2.35; 145 20.637,2.35; 146 20.637,-2.35; 147 21.273,2.35; 148 21.273,-2.35; 149 21.907,2.35; 150 21.907,-2.35; 151 22.543,2.35; 152 22.543,-2.35; 153 23.177,2.35; 154 23.177,-2.35; 155 23.812,2.35; 156 23.812,-2.35; 157 24.448,2.35; 158 24.448,-2.35; 159 25.082,2.35; 160 25.082,-2.35
smd 2.5 x 2: M1 -28.15,0; M2 28.15,0
hole 0.9 at -26.335,0
hole 0.7 at 26.335,0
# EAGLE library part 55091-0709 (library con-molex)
0.635 mm PITCH B TO B CONN. Source: http://www.molex.com/pdm_docs/sd/550911609_sd.pdf

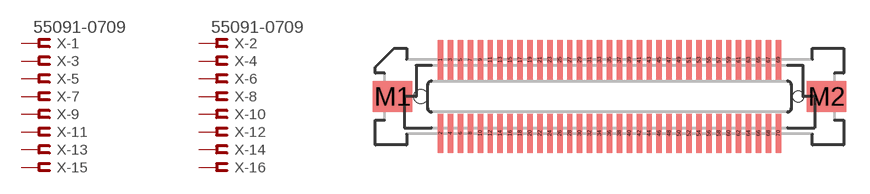
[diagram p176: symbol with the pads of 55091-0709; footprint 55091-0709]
Designator prefix X; gates -1=FV -2=FV -3=F -4=F -5=F -6=F -7=F -8=F -9=F -10=F -11=F -12=F -13=F -14=F -15=F -16=F -17=F -18=F -19=F -20=F -21=F -22=F -23=F -24=F -25=F -26=F -27=F -28=F -29=F -30=F -31=F -32=F -33=F -34=F -35=F -36=F -37=F -38=F -39=F -40=F -41=F -42=F -43=F -44=F -45=F -46=F -47=F -48=F -49=F -50=F -51=F -52=F -53=F -54=F -55=F -56=F -57=F -58=F -59=F -60=F -61=F -62=F -63=F -64=F -65=F -66=F -67=F -68=F -69=F -70=F

## 55091-0709 (OC_FARNELL: unknown; OC_NEWARK: unknown)  [55091-0709]
1  -1:S  pas
2  -2:S  pas
3  -3:S  pas
4  -4:S  pas
5  -5:S  pas
6  -6:S  pas
7  -7:S  pas
8  -8:S  pas
9  -9:S  pas
10  -10:S  pas
11  -11:S  pas
12  -12:S  pas
13  -13:S  pas
14  -14:S  pas
15  -15:S  pas
16  -16:S  pas
17  -17:S  pas
18  -18:S  pas
19  -19:S  pas
20  -20:S  pas
21  -21:S  pas
22  -22:S  pas
23  -23:S  pas
24  -24:S  pas
25  -25:S  pas
26  -26:S  pas
27  -27:S  pas
28  -28:S  pas
29  -29:S  pas
30  -30:S  pas
31  -31:S  pas
32  -32:S  pas
33  -33:S  pas
34  -34:S  pas
35  -35:S  pas
36  -36:S  pas
37  -37:S  pas
38  -38:S  pas
39  -39:S  pas
40  -40:S  pas
41  -41:S  pas
42  -42:S  pas
43  -43:S  pas
44  -44:S  pas
45  -45:S  pas
46  -46:S  pas
47  -47:S  pas
48  -48:S  pas
49  -49:S  pas
50  -50:S  pas
51  -51:S  pas
52  -52:S  pas
53  -53:S  pas
54  -54:S  pas
55  -55:S  pas
56  -56:S  pas
57  -57:S  pas
58  -58:S  pas
59  -59:S  pas
60  -60:S  pas
61  -61:S  pas
62  -62:S  pas
63  -63:S  pas
64  -64:S  pas
65  -65:S  pas
66  -66:S  pas
67  -67:S  pas
68  -68:S  pas
69  -69:S  pas
70  -70:S  pas

## Footprint 55091-0709 (pad centres in mm)
0.635 mm PITCH B TO B CONN. Source: http://www.molex.com/pdm_docs/sd/550911609_sd.pdf
smd 0.35 x 2.5: 1 -10.795,2.35; 2 -10.795,-2.35; 3 -10.16,2.35; 4 -10.16,-2.35; 5 -9.525,2.35; 6 -9.525,-2.35; 7 -8.89,2.35; 8 -8.89,-2.35; 9 -8.255,2.35; 10 -8.255,-2.35; 11 -7.62,2.35; 12 -7.62,-2.35; 13 -6.985,2.35; 14 -6.985,-2.35; 15 -6.35,2.35; 16 -6.35,-2.35; 17 -5.715,2.35; 18 -5.715,-2.35; 19 -5.08,2.35; 20 -5.08,-2.35; 21 -4.445,2.35; 22 -4.445,-2.35; 23 -3.81,2.35; 24 -3.81,-2.35; 25 -3.175,2.35; 26 -3.175,-2.35; 27 -2.54,2.35; 28 -2.54,-2.35; 29 -1.905,2.35; 30 -1.905,-2.35; 31 -1.27,2.35; 32 -1.27,-2.35; 33 -0.635,2.35; 34 -0.635,-2.35; 35 0,2.35; 36 0,-2.35; 37 0.635,2.35; 38 0.635,-2.35; 39 1.27,2.35; 40 1.27,-2.35; 41 1.905,2.35; 42 1.905,-2.35; 43 2.54,2.35; 44 2.54,-2.35; 45 3.175,2.35; 46 3.175,-2.35; 47 3.81,2.35; 48 3.81,-2.35; 49 4.445,2.35; 50 4.445,-2.35; 51 5.08,2.35; 52 5.08,-2.35; 53 5.715,2.35; 54 5.715,-2.35; 55 6.35,2.35; 56 6.35,-2.35; 57 6.985,2.35; 58 6.985,-2.35; 59 7.62,2.35; 60 7.62,-2.35; 61 8.255,2.35; 62 8.255,-2.35; 63 8.89,2.35; 64 8.89,-2.35; 65 9.525,2.35; 66 9.525,-2.35; 67 10.16,2.35; 68 10.16,-2.35; 69 10.795,2.35; 70 10.795,-2.35
smd 2.5 x 2: M1 -13.863,0; M2 13.863,0
hole 0.9 at -12.05,0
hole 0.7 at 12.05,0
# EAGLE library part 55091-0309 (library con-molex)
0.635 mm PITCH B TO B CONN. Source: http://www.molex.com/pdm_docs/sd/550911609_sd.pdf

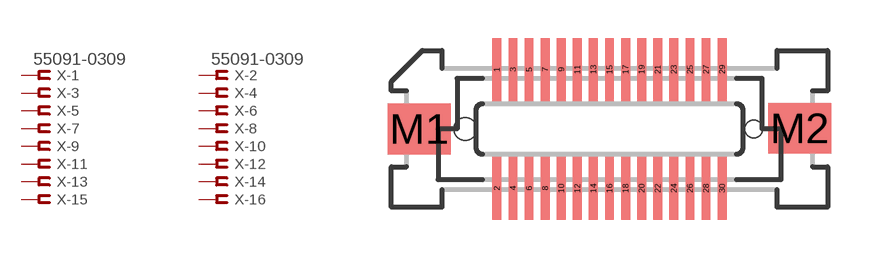
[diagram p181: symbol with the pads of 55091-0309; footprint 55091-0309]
Designator prefix X; gates -1=FV -2=FV -3=F -4=F -5=F -6=F -7=F -8=F -9=F -10=F -11=F -12=F -13=F -14=F -15=F -16=F -17=F -18=F -19=F -20=F -21=F -22=F -23=F -24=F -25=F -26=F -27=F -28=F -29=F -30=F

## 55091-0309 (OC_FARNELL: unknown; OC_NEWARK: unknown)  [55091-0309]
1  -1:S  pas
2  -2:S  pas
3  -3:S  pas
4  -4:S  pas
5  -5:S  pas
6  -6:S  pas
7  -7:S  pas
8  -8:S  pas
9  -9:S  pas
10  -10:S  pas
11  -11:S  pas
12  -12:S  pas
13  -13:S  pas
14  -14:S  pas
15  -15:S  pas
16  -16:S  pas
17  -17:S  pas
18  -18:S  pas
19  -19:S  pas
20  -20:S  pas
21  -21:S  pas
22  -22:S  pas
23  -23:S  pas
24  -24:S  pas
25  -25:S  pas
26  -26:S  pas
27  -27:S  pas
28  -28:S  pas
29  -29:S  pas
30  -30:S  pas

## Footprint 55091-0309 (pad centres in mm)
0.635 mm PITCH B TO B CONN. Source: http://www.molex.com/pdm_docs/sd/550911609_sd.pdf
smd 0.35 x 2.5: 1 -4.445,2.35; 2 -4.445,-2.35; 3 -3.81,2.35; 4 -3.81,-2.35; 5 -3.175,2.35; 6 -3.175,-2.35; 7 -2.54,2.35; 8 -2.54,-2.35; 9 -1.905,2.35; 10 -1.905,-2.35; 11 -1.27,2.35; 12 -1.27,-2.35; 13 -0.635,2.35; 14 -0.635,-2.35; 15 0,2.35; 16 0,-2.35; 17 0.635,2.35; 18 0.635,-2.35; 19 1.27,2.35; 20 1.27,-2.35; 21 1.905,2.35; 22 1.905,-2.35; 23 2.54,2.35; 24 2.54,-2.35; 25 3.175,2.35; 26 3.175,-2.35; 27 3.81,2.35; 28 3.81,-2.35; 29 4.445,2.35; 30 4.445,-2.35
smd 2.5 x 2: M1 -7.513,0; M2 7.513,0.025
hole 0.9 at -5.7,0
hole 0.7 at 5.7,0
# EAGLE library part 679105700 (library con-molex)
MINI PCI EXPRESS CONNECTOR 0.8MM PITCH, 52 CIRCUIT Source: http://www.molex.com/pdm_docs/sd/679105700_sd.pdf

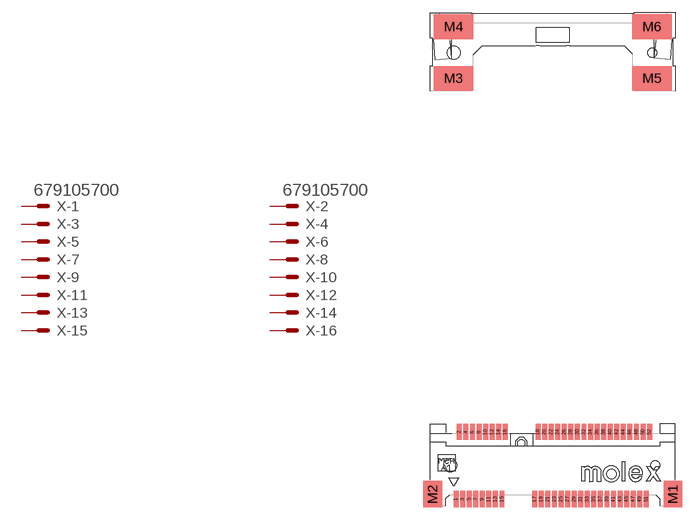
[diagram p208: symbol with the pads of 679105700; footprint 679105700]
Designator prefix X; gates -1=MV -2=MV -3=M -4=M -5=M -6=M -7=M -8=M -9=M -10=M -11=M -12=M -13=M -14=M -15=M -16=M -17=M -18=M -19=M -20=M -21=M -22=M -23=M -24=M -25=M -26=M -27=M -28=M -29=M -30=M -31=M -32=M -33=M -34=M -35=M -36=M -37=M -38=M -39=M -40=M -41=M -42=M -43=M -44=M -45=M -46=M -47=M -48=M -49=M -50=M -51=M -52=M

## 679105700 (MPN: 67910-5700; OC_FARNELL: unknown; OC_NEWARK: 93M2128)  [679105700]
1  -1:S  pas
2  -2:S  pas
3  -3:S  pas
4  -4:S  pas
5  -5:S  pas
6  -6:S  pas
7  -7:S  pas
8  -8:S  pas
9  -9:S  pas
10  -10:S  pas
11  -11:S  pas
12  -12:S  pas
13  -13:S  pas
14  -14:S  pas
15  -15:S  pas
16  -16:S  pas
17  -17:S  pas
18  -18:S  pas
19  -19:S  pas
20  -20:S  pas
21  -21:S  pas
22  -22:S  pas
23  -23:S  pas
24  -24:S  pas
25  -25:S  pas
26  -26:S  pas
27  -27:S  pas
28  -28:S  pas
29  -29:S  pas
30  -30:S  pas
31  -31:S  pas
32  -32:S  pas
33  -33:S  pas
34  -34:S  pas
35  -35:S  pas
36  -36:S  pas
37  -37:S  pas
38  -38:S  pas
39  -39:S  pas
40  -40:S  pas
41  -41:S  pas
42  -42:S  pas
43  -43:S  pas
44  -44:S  pas
45  -45:S  pas
46  -46:S  pas
47  -47:S  pas
48  -48:S  pas
49  -49:S  pas
50  -50:S  pas
51  -51:S  pas
52  -52:S  pas

## Footprint 679105700 (pad centres in mm)
MINI PCI EXPRESS CONNECTOR 0.8MM PITCH, 52 CIRCUIT Source: http://www.molex.com/pdm_docs/sd/679105700_sd.pdf
smd 0.6 x 2: 1 0.7,-4.1; 2 1.1,4.1; 3 1.5,-4.1; 4 1.9,4.1; 5 2.3,-4.1; 6 2.7,4.1; 7 3.1,-4.1; 8 3.5,4.1; 9 3.9,-4.1; 10 4.3,4.1; 11 4.7,-4.1; 12 5.1,4.1; 13 5.5,-4.1; 14 5.9,4.1; 15 6.3,-4.1; 16 6.7,4.1; 17 10.3,-4.1; 18 10.7,4.1; 19 11.1,-4.1; 20 11.5,4.1; 21 11.9,-4.1; 22 12.3,4.1; 23 12.7,-4.1; 24 13.1,4.1; 25 13.5,-4.1; 26 13.9,4.1; 27 14.3,-4.1; 28 14.7,4.1; 29 15.1,-4.1; 30 15.5,4.1; 31 15.9,-4.1; 32 16.3,4.1; 33 16.7,-4.1; 34 17.1,4.1; 35 17.5,-4.1; 36 17.9,4.1; 37 18.3,-4.1; 38 18.7,4.1; 39 19.1,-4.1; 40 19.5,4.1; 41 19.9,-4.1; 42 20.3,4.1; 43 20.7,-4.1; 44 21.1,4.1; 45 21.5,-4.1; 46 21.9,4.1; 47 22.3,-4.1; 48 22.7,4.1; 49 23.1,-4.1; 50 23.5,4.1; 51 23.9,-4.1; 52 24.3,4.1
smd 2.3 x 3.2: M1 27.15,-3.5; M2 -2.15,-3.5
smd 4.8 x 3: M3 0.4,47.25; M4 0.4,53.55; M5 24.6,47.25; M6 24.6,53.55
hole 1.6 at 0,0
hole 1.1 at 25,0
hole 1.6 at 0.4,50.4
hole 1.1 at 24.6,50.4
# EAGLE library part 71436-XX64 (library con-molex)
Board-to-Board Connector 1.00mm (.039") Mezzanine IEEE 1386 Plug - Dual Row, SMT, Vertical Stacking Source: http://www.molex.com/product/micro/71436.html

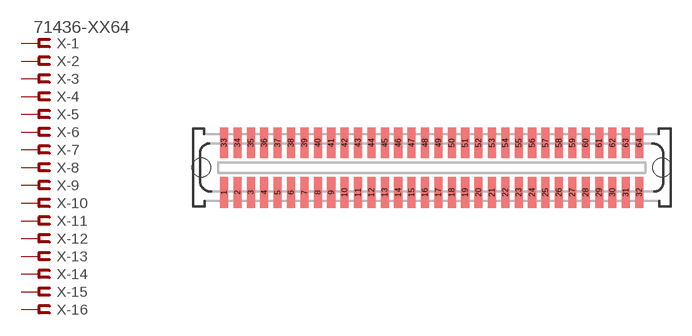
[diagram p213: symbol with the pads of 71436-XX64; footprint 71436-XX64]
Designator prefix X; gates -1=FV -2=F -3=F -4=F -5=F -6=F -7=F -8=F -9=F -10=F -11=F -12=F -13=F -14=F -15=F -16=F -17=F -18=F -19=F -20=F -21=F -22=F -23=F -24=F -25=F -26=F -27=F -28=F -29=F -30=F -31=F -32=F -33=F -34=F -35=F -36=F -37=F -38=F -39=F -40=F -41=F -42=F -43=F -44=F -45=F -46=F -47=F -48=F -49=F -50=F -51=F -52=F -53=F -54=F -55=F -56=F -57=F -58=F -59=F -60=F -61=F -62=F -63=F -64=F

## 71436-XX64 (OC_FARNELL: unknown; OC_NEWARK: unknown)  [71436-XX64]
1  -1:S  pas
2  -2:S  pas
3  -3:S  pas
4  -4:S  pas
5  -5:S  pas
6  -6:S  pas
7  -7:S  pas
8  -8:S  pas
9  -9:S  pas
10  -10:S  pas
11  -11:S  pas
12  -12:S  pas
13  -13:S  pas
14  -14:S  pas
15  -15:S  pas
16  -16:S  pas
17  -17:S  pas
18  -18:S  pas
19  -19:S  pas
20  -20:S  pas
21  -21:S  pas
22  -22:S  pas
23  -23:S  pas
24  -24:S  pas
25  -25:S  pas
26  -26:S  pas
27  -27:S  pas
28  -28:S  pas
29  -29:S  pas
30  -30:S  pas
31  -31:S  pas
32  -32:S  pas
33  -33:S  pas
34  -34:S  pas
35  -35:S  pas
36  -36:S  pas
37  -37:S  pas
38  -38:S  pas
39  -39:S  pas
40  -40:S  pas
41  -41:S  pas
42  -42:S  pas
43  -43:S  pas
44  -44:S  pas
45  -45:S  pas
46  -46:S  pas
47  -47:S  pas
48  -48:S  pas
49  -49:S  pas
50  -50:S  pas
51  -51:S  pas
52  -52:S  pas
53  -53:S  pas
54  -54:S  pas
55  -55:S  pas
56  -56:S  pas
57  -57:S  pas
58  -58:S  pas
59  -59:S  pas
60  -60:S  pas
61  -61:S  pas
62  -62:S  pas
63  -63:S  pas
64  -64:S  pas

## Footprint 71436-XX64 (pad centres in mm)
Board-to-Board Connector 1.00mm (.039") Mezzanine IEEE 1386 Plug - Dual Row, SMT, Vertical Stacking Source: http://www.molex.com/product/micro/71436.html
smd 0.6 x 2.3: 1 -15.5,-1.85; 2 -14.5,-1.85; 3 -13.5,-1.85; 4 -12.5,-1.85; 5 -11.5,-1.85; 6 -10.5,-1.85; 7 -9.5,-1.85; 8 -8.5,-1.85; 9 -7.5,-1.85; 10 -6.5,-1.85; 11 -5.5,-1.85; 12 -4.5,-1.85; 13 -3.5,-1.85; 14 -2.5,-1.85; 15 -1.5,-1.85; 16 -0.5,-1.85; 17 0.5,-1.85; 18 1.5,-1.85; 19 2.5,-1.85; 20 3.5,-1.85; 21 4.5,-1.85; 22 5.5,-1.85; 23 6.5,-1.85; 24 7.5,-1.85; 25 8.5,-1.85; 26 9.5,-1.85; 27 10.5,-1.85; 28 11.5,-1.85; 29 12.5,-1.85; 30 13.5,-1.85; 31 14.5,-1.85; 32 15.5,-1.85; 33 -15.5,1.85; 34 -14.5,1.85; 35 -13.5,1.85; 36 -12.5,1.85; 37 -11.5,1.85; 38 -10.5,1.85; 39 -9.5,1.85; 40 -8.5,1.85; 41 -7.5,1.85; 42 -6.5,1.85; 43 -5.5,1.85; 44 -4.5,1.85; 45 -3.5,1.85; 46 -2.5,1.85; 47 -1.5,1.85; 48 -0.5,1.85; 49 0.5,1.85; 50 1.5,1.85; 51 2.5,1.85; 52 3.5,1.85; 53 4.5,1.85; 54 5.5,1.85; 55 6.5,1.85; 56 7.5,1.85; 57 8.5,1.85; 58 9.5,1.85; 59 10.5,1.85; 60 11.5,1.85; 61 12.5,1.85; 62 13.5,1.85; 63 14.5,1.85; 64 15.5,1.85
hole 1.4 at -17.2,0
hole 1.4 at 17.2,0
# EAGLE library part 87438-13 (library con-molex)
Wire-to-Board 1.50mm (.059") Pitch Header - Right Angle, SMT, Shrouded Source: http://www.molex.com/product/micro/87438.html

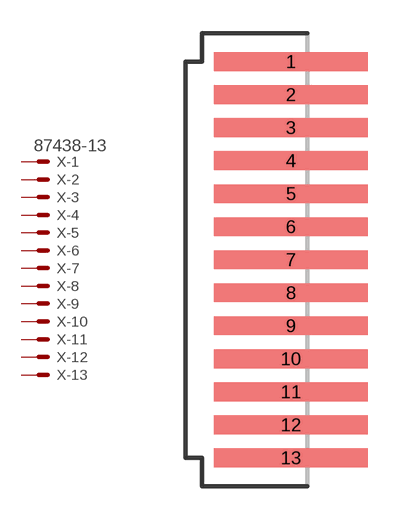
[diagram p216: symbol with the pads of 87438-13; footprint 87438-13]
Designator prefix X; gates -1=MV -2=M -3=M -4=M -5=M -6=M -7=M -8=M -9=M -10=M -11=M -12=M -13=M

## 87438-13 (MPN: 87438-1343; OC_FARNELL: unknown; OC_NEWARK: 94M1104)  [87438-13]
1  -1:S  pas
2  -2:S  pas
3  -3:S  pas
4  -4:S  pas
5  -5:S  pas
6  -6:S  pas
7  -7:S  pas
8  -8:S  pas
9  -9:S  pas
10  -10:S  pas
11  -11:S  pas
12  -12:S  pas
13  -13:S  pas

## Footprint 87438-13 (pad centres in mm)
Wire-to-Board 1.50mm (.059") Pitch Header - Right Angle, SMT, Shrouded Source: http://www.molex.com/product/micro/87438.html
smd 7 x 0.85: 1 0,9; 2 0,7.5; 3 0,6; 4 0,4.5; 5 0,3; 6 0,1.5; 7 0,0; 8 0,-1.5; 9 0,-3; 10 0,-4.5; 11 0,-6; 12 0,-7.5; 13 0,-9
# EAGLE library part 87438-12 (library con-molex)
Wire-to-Board 1.50mm (.059") Pitch Header - Right Angle, SMT, Shrouded Source: http://www.molex.com/product/micro/87438.html

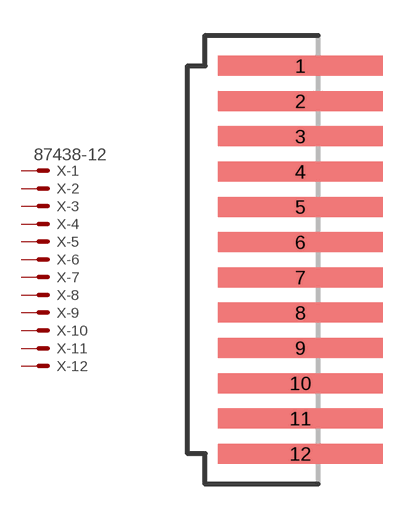
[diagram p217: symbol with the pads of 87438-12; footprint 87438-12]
Designator prefix X; gates -1=MV -2=M -3=M -4=M -5=M -6=M -7=M -8=M -9=M -10=M -11=M -12=M

## 87438-12 (OC_FARNELL: 1711334; OC_NEWARK: unknown)  [87438-12]
1  -1:S  pas
2  -2:S  pas
3  -3:S  pas
4  -4:S  pas
5  -5:S  pas
6  -6:S  pas
7  -7:S  pas
8  -8:S  pas
9  -9:S  pas
10  -10:S  pas
11  -11:S  pas
12  -12:S  pas

## Footprint 87438-12 (pad centres in mm)
Wire-to-Board 1.50mm (.059") Pitch Header - Right Angle, SMT, Shrouded Source: http://www.molex.com/product/micro/87438.html
smd 7 x 0.85: 1 0,8.25; 2 0,6.75; 3 0,5.25; 4 0,3.75; 5 0,2.25; 6 0,0.75; 7 0,-0.75; 8 0,-2.25; 9 0,-3.75; 10 0,-5.25; 11 0,-6.75; 12 0,-8.25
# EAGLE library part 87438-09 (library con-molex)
Wire-to-Board 1.50mm (.059") Pitch Header - Right Angle, SMT, Shrouded Source: http://www.molex.com/product/micro/87438.html

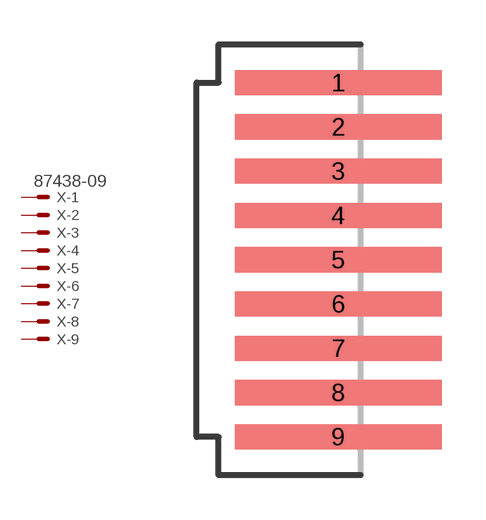
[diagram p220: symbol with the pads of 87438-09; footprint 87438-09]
Designator prefix X; gates -1=MV -2=M -3=M -4=M -5=M -6=M -7=M -8=M -9=M

## 87438-09 (OC_FARNELL: unknown; OC_NEWARK: unknown)  [87438-09]
1  -1:S  pas
2  -2:S  pas
3  -3:S  pas
4  -4:S  pas
5  -5:S  pas
6  -6:S  pas
7  -7:S  pas
8  -8:S  pas
9  -9:S  pas

## Footprint 87438-09 (pad centres in mm)
Wire-to-Board 1.50mm (.059") Pitch Header - Right Angle, SMT, Shrouded Source: http://www.molex.com/product/micro/87438.html
smd 7 x 0.85: 1 0,6; 2 0,4.5; 3 0,3; 4 0,1.5; 5 0,0; 6 0,-1.5; 7 0,-3; 8 0,-4.5; 9 0,-6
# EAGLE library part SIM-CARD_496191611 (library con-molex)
MICROSD/SIM COMBO SOCKET RIGHT ENTRY TYPE Source: 1648045.pdf

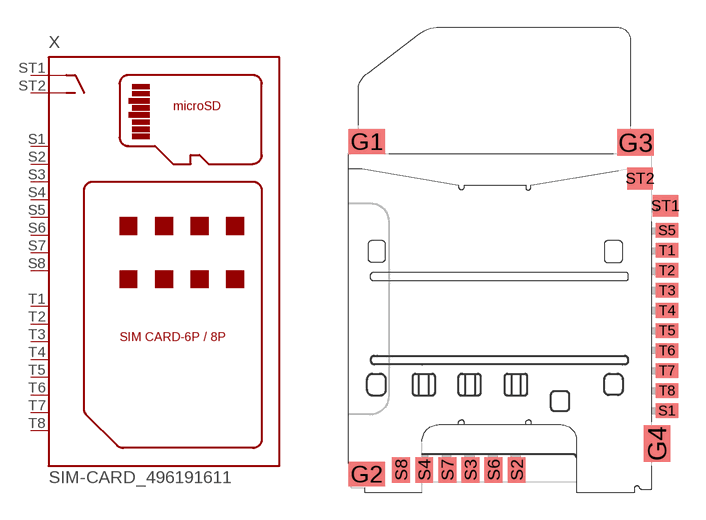
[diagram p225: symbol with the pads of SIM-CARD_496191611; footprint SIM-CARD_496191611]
Designator prefix X

## SIM-CARD_496191611  [SIM-CARD_496191611]
S1  S1  pas
S2  S2  pas
S3  S3  pas
S4  S4  pas
S5  S5  pas
S6  S6  pas
S7  S7  pas
S8  S8  pas
ST1  ST1  pas
ST2  ST2  pas
T1  T1  pas
T2  T2  pas
T3  T3  pas
T4  T4  pas
T5  T5  pas
T6  T6  pas
T7  T7  pas
T8  T8  pas

## Footprint SIM-CARD_496191611 (pad centres in mm)
1.10mm/1.27mm Pitch microSD/SIM Card Combo Connector 8-Pin microSD, Reverse Mount with Detect Switch, and 8-Pin SIM, Normal Mount, Right Entry Type Source: http://www.molex.com 1648045.pdf
smd 2 x 1.35: G1 1,18.938; G2 1,0.675
smd 2 x 1.45: G3 15.75,18.887
smd 1.45 x 2: G4 16.925,2.35
smd 1.25 x 0.8: S1 17.475,4.162; S5 17.475,14.062; T1 17.475,12.963; T2 17.475,11.863; T3 17.475,10.762; T4 17.475,9.662; T5 17.475,8.562; T6 17.475,7.463; T7 17.475,6.362; T8 17.475,5.263
smd 0.98 x 1.4: S2 9.225,0.9; S3 6.685,0.9; S4 4.145,0.9; S6 7.955,0.9; S7 5.415,0.9; S8 2.875,0.9
smd 1.4 x 1.2: ST1 17.4,15.412; ST2 16,16.913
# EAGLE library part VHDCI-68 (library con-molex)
VHDCI RIGHT ANGLE ASSEMBLY 68-Pin 73412-0110 86-Pin-VHDCI-Anschluss (rechtwinklig) Source: Data sheet

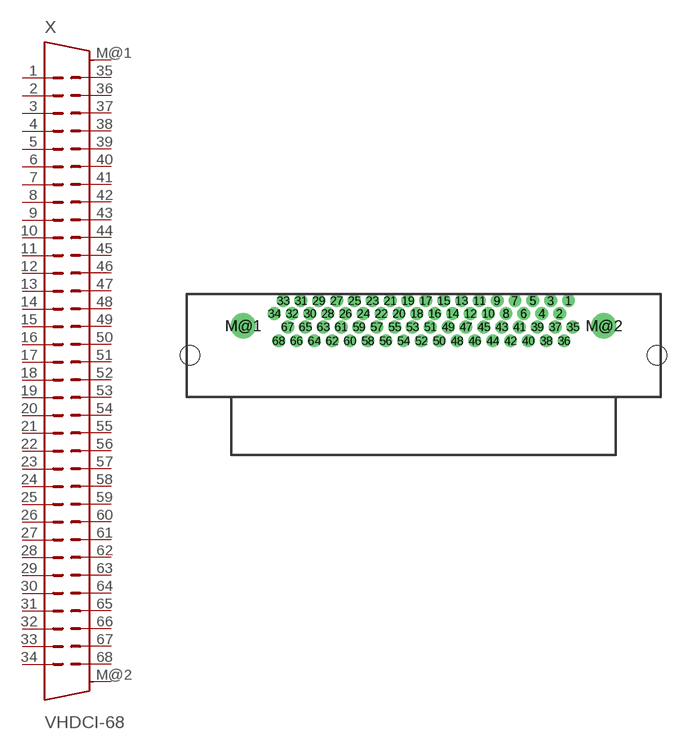
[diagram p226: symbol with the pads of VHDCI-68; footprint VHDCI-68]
Designator prefix X

## VHDCI-68  [VHDCI-68]
1  1  pas
2  2  pas
3  3  pas
4  4  pas
5  5  pas
6  6  pas
7  7  pas
8  8  pas
9  9  pas
10  10  pas
11  11  pas
12  12  pas
13  13  pas
14  14  pas
15  15  pas
16  16  pas
17  17  pas
18  18  pas
19  19  pas
20  20  pas
21  21  pas
22  22  pas
23  23  pas
24  24  pas
25  25  pas
26  26  pas
27  27  pas
28  28  pas
29  29  pas
30  30  pas
31  31  pas
32  32  pas
33  33  pas
34  34  pas
35  35  pas
36  36  pas
37  37  pas
38  38  pas
39  39  pas
40  40  pas
41  41  pas
42  42  pas
43  43  pas
44  44  pas
45  45  pas
46  46  pas
47  47  pas
48  48  pas
49  49  pas
50  50  pas
51  51  pas
52  52  pas
53  53  pas
54  54  pas
55  55  pas
56  56  pas
57  57  pas
58  58  pas
59  59  pas
60  60  pas
61  61  pas
62  62  pas
63  63  pas
64  64  pas
65  65  pas
66  66  pas
67  67  pas
68  68  pas
M@1  S  pas
M@2  S  pas

## Footprint VHDCI-68 (pad centres in mm)
86-Pin-VHDCI-Anschluss (rechtwinklig) 73412-0110 Source: Data sheet
drill 0.65 pad 1: 1 13.005,2.25; 2 12.205,1.1; 3 11.405,2.25; 4 10.605,1.1; 5 9.805,2.25; 6 9.005,1.1; 7 8.205,2.25; 8 7.405,1.1; 9 6.605,2.25; 10 5.805,1.1; 11 5.005,2.25; 12 4.205,1.1; 13 3.405,2.25; 14 2.605,1.1; 15 1.805,2.25; 16 1.005,1.1; 17 0.205,2.25; 18 -0.595,1.1; 19 -1.395,2.25; 20 -2.195,1.1; 21 -2.995,2.25; 22 -3.795,1.1; 23 -4.595,2.25; 24 -5.395,1.1; 25 -6.195,2.25; 26 -6.995,1.1; 27 -7.795,2.25; 28 -8.595,1.1; 29 -9.395,2.25; 30 -10.195,1.1; 31 -10.995,2.25; 32 -11.795,1.1; 33 -12.595,2.25; 34 -13.395,1.1; 35 13.405,-0.1; 36 12.605,-1.35; 37 11.805,-0.1; 38 11.005,-1.35; 39 10.205,-0.1; 40 9.405,-1.35; 41 8.605,-0.1; 42 7.805,-1.35; 43 7.005,-0.1; 44 6.205,-1.35; 45 5.405,-0.1; 46 4.605,-1.35; 47 3.805,-0.1; 48 3.005,-1.35; 49 2.205,-0.1; 50 1.405,-1.35; 51 0.605,-0.1; 52 -0.195,-1.35; 53 -0.995,-0.1; 54 -1.795,-1.35; 55 -2.595,-0.1; 56 -3.395,-1.35; 57 -4.195,-0.1; 58 -4.995,-1.35; 59 -5.795,-0.1; 60 -6.595,-1.35; 61 -7.395,-0.1; 62 -8.195,-1.35; 63 -8.995,-0.1; 64 -9.795,-1.35; 65 -10.595,-0.1; 66 -11.395,-1.35; 67 -12.195,-0.1; 68 -12.995,-1.35
drill 1.2 pad 2.25: M@1 -16.175,0; M@2 16.175,0
hole 1.75 at 20.95,-2.63
hole 1.75 at -20.95,-2.63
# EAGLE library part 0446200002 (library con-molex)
RJ-45 INVERTED MODULAR JACK ASSEMBLY WITH RJ-11 KEEPOUT FEATURE Source: Data sheet MOLEX 0446200002 BUCHSE, RJ45, GESCHIRMT Source: Farnell

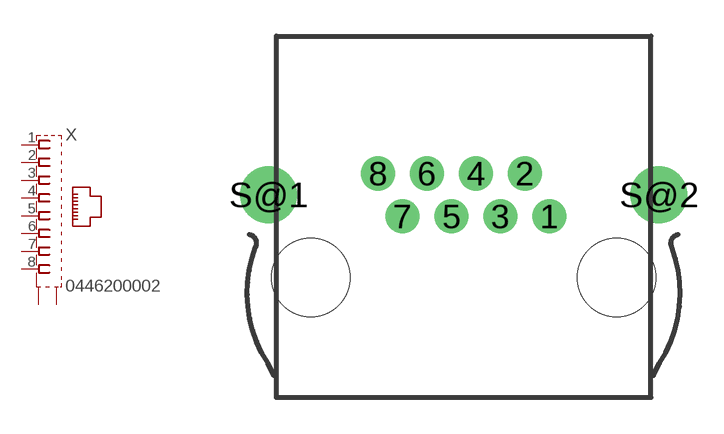
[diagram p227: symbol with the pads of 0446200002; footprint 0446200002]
Designator prefix X

## 0446200002 (MF: MOLEX; MPN: 0446200002; OC_FARNELL: 9251910)  [0446200002]
1  1  pas
2  2  pas
3  3  pas
4  4  pas
5  5  pas
6  6  pas
7  7  pas
8  8  pas
S@1  S1  pas
S@2  S2  pas

## Footprint 0446200002 (pad centres in mm)
RJ-45 INVERTED MODULAR JACK ASSEMBLY WITH RJ-11 KEEPOUT FEATURE Source: Data sheet MOLEX 0446200002 BUCHSE, RJ45, GESCHIRMT Source: Farnell
drill 0.889 pad 1.422: 1 3.556,2.54; 2 2.54,4.318; 3 1.524,2.54; 4 0.508,4.318; 5 -0.508,2.54; 6 -1.524,4.318; 7 -2.54,2.54; 8 -3.556,4.318
drill 1.575 pad 2.286: S@1 -8.103,3.429; S@2 8.103,3.429
hole 3.251 at 6.35,0
hole 3.251 at -6.35,0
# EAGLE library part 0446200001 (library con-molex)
RJ-45 INVERTED MODULAR JACK ASSEMBLY WITH RJ-11 KEEPOUT FEATURE Source: Data sheet

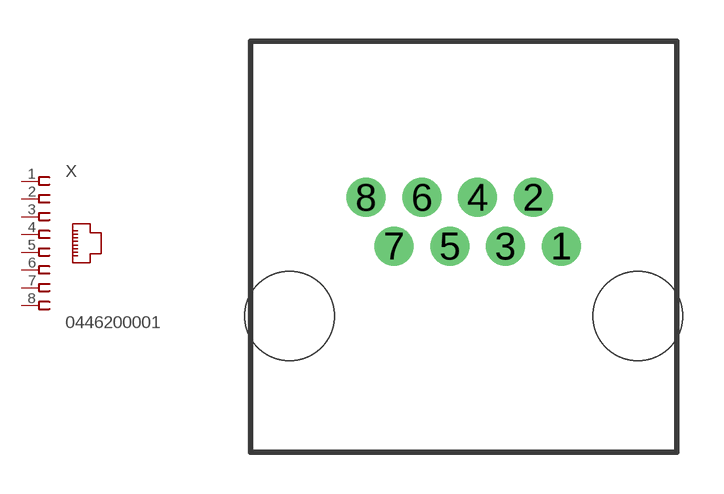
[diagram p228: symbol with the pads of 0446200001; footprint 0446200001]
Designator prefix X

## 0446200001 (OC_FARNELL: unknown)  [0446200001]
1  1  pas
2  2  pas
3  3  pas
4  4  pas
5  5  pas
6  6  pas
7  7  pas
8  8  pas

## Footprint 0446200001 (pad centres in mm)
RJ-45 INVERTED MODULAR JACK ASSEMBLY WITH RJ-11 KEEPOUT FEATURE Source: Data sheet
drill 0.889 pad 1.422: 1 3.556,2.54; 2 2.54,4.318; 3 1.524,2.54; 4 0.508,4.318; 5 -0.508,2.54; 6 -1.524,4.318; 7 -2.54,2.54; 8 -3.556,4.318
hole 3.251 at 6.35,0
hole 3.251 at -6.35,0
